VERSION 5.4 ;
NAMESCASESENSITIVE ON ;
BUSBITCHARS "[]" ;
DIVIDERCHAR "/" ;
UNITS
  DATABASE MICRONS 2000 ;
END UNITS
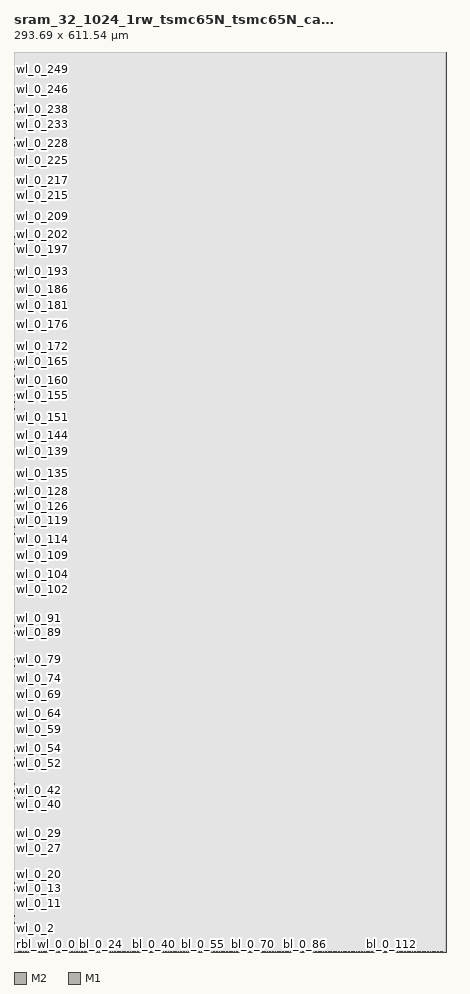
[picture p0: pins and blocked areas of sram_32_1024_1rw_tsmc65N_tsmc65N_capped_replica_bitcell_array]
MACRO sram_32_1024_1rw_tsmc65N_tsmc65N_capped_replica_bitcell_array
   CLASS BLOCK ;
   SIZE 293.69 BY 611.54 ;
   SYMMETRY X Y R90 ;
   PIN rbl_bl_0_0
      DIRECTION INOUT ;
      PORT
         LAYER M2 ;
         RECT  3.06 0.0 3.16 0.1 ;
      END
   END rbl_bl_0_0
   PIN rbl_br_0_0
      DIRECTION INOUT ;
      PORT
         LAYER M2 ;
         RECT  4.06 0.0 4.16 0.1 ;
      END
   END rbl_br_0_0
   PIN bl_0_0
      DIRECTION INOUT ;
      PORT
         LAYER M2 ;
         RECT  5.3 0.0 5.4 0.1 ;
      END
   END bl_0_0
   PIN br_0_0
      DIRECTION INOUT ;
      PORT
         LAYER M2 ;
         RECT  6.3 0.0 6.4 0.1 ;
      END
   END br_0_0
   PIN bl_0_1
      DIRECTION INOUT ;
      PORT
         LAYER M2 ;
         RECT  7.54 0.0 7.64 0.1 ;
      END
   END bl_0_1
   PIN br_0_1
      DIRECTION INOUT ;
      PORT
         LAYER M2 ;
         RECT  8.54 0.0 8.64 0.1 ;
      END
   END br_0_1
   PIN bl_0_2
      DIRECTION INOUT ;
      PORT
         LAYER M2 ;
         RECT  9.78 0.0 9.88 0.1 ;
      END
   END bl_0_2
   PIN br_0_2
      DIRECTION INOUT ;
      PORT
         LAYER M2 ;
         RECT  10.78 0.0 10.88 0.1 ;
      END
   END br_0_2
   PIN bl_0_3
      DIRECTION INOUT ;
      PORT
         LAYER M2 ;
         RECT  12.02 0.0 12.12 0.1 ;
      END
   END bl_0_3
   PIN br_0_3
      DIRECTION INOUT ;
      PORT
         LAYER M2 ;
         RECT  13.02 0.0 13.12 0.1 ;
      END
   END br_0_3
   PIN bl_0_4
      DIRECTION INOUT ;
      PORT
         LAYER M2 ;
         RECT  14.26 0.0 14.36 0.1 ;
      END
   END bl_0_4
   PIN br_0_4
      DIRECTION INOUT ;
      PORT
         LAYER M2 ;
         RECT  15.26 0.0 15.36 0.1 ;
      END
   END br_0_4
   PIN bl_0_5
      DIRECTION INOUT ;
      PORT
         LAYER M2 ;
         RECT  16.5 0.0 16.6 0.1 ;
      END
   END bl_0_5
   PIN br_0_5
      DIRECTION INOUT ;
      PORT
         LAYER M2 ;
         RECT  17.5 0.0 17.6 0.1 ;
      END
   END br_0_5
   PIN bl_0_6
      DIRECTION INOUT ;
      PORT
         LAYER M2 ;
         RECT  18.74 0.0 18.84 0.1 ;
      END
   END bl_0_6
   PIN br_0_6
      DIRECTION INOUT ;
      PORT
         LAYER M2 ;
         RECT  19.74 0.0 19.84 0.1 ;
      END
   END br_0_6
   PIN bl_0_7
      DIRECTION INOUT ;
      PORT
         LAYER M2 ;
         RECT  20.98 0.0 21.08 0.1 ;
      END
   END bl_0_7
   PIN br_0_7
      DIRECTION INOUT ;
      PORT
         LAYER M2 ;
         RECT  21.98 0.0 22.08 0.1 ;
      END
   END br_0_7
   PIN bl_0_8
      DIRECTION INOUT ;
      PORT
         LAYER M2 ;
         RECT  23.22 0.0 23.32 0.1 ;
      END
   END bl_0_8
   PIN br_0_8
      DIRECTION INOUT ;
      PORT
         LAYER M2 ;
         RECT  24.22 0.0 24.32 0.1 ;
      END
   END br_0_8
   PIN bl_0_9
      DIRECTION INOUT ;
      PORT
         LAYER M2 ;
         RECT  25.46 0.0 25.56 0.1 ;
      END
   END bl_0_9
   PIN br_0_9
      DIRECTION INOUT ;
      PORT
         LAYER M2 ;
         RECT  26.46 0.0 26.56 0.1 ;
      END
   END br_0_9
   PIN bl_0_10
      DIRECTION INOUT ;
      PORT
         LAYER M2 ;
         RECT  27.7 0.0 27.8 0.1 ;
      END
   END bl_0_10
   PIN br_0_10
      DIRECTION INOUT ;
      PORT
         LAYER M2 ;
         RECT  28.7 0.0 28.8 0.1 ;
      END
   END br_0_10
   PIN bl_0_11
      DIRECTION INOUT ;
      PORT
         LAYER M2 ;
         RECT  29.94 0.0 30.04 0.1 ;
      END
   END bl_0_11
   PIN br_0_11
      DIRECTION INOUT ;
      PORT
         LAYER M2 ;
         RECT  30.94 0.0 31.04 0.1 ;
      END
   END br_0_11
   PIN bl_0_12
      DIRECTION INOUT ;
      PORT
         LAYER M2 ;
         RECT  32.18 0.0 32.28 0.1 ;
      END
   END bl_0_12
   PIN br_0_12
      DIRECTION INOUT ;
      PORT
         LAYER M2 ;
         RECT  33.18 0.0 33.28 0.1 ;
      END
   END br_0_12
   PIN bl_0_13
      DIRECTION INOUT ;
      PORT
         LAYER M2 ;
         RECT  34.42 0.0 34.52 0.1 ;
      END
   END bl_0_13
   PIN br_0_13
      DIRECTION INOUT ;
      PORT
         LAYER M2 ;
         RECT  35.42 0.0 35.52 0.1 ;
      END
   END br_0_13
   PIN bl_0_14
      DIRECTION INOUT ;
      PORT
         LAYER M2 ;
         RECT  36.66 0.0 36.76 0.1 ;
      END
   END bl_0_14
   PIN br_0_14
      DIRECTION INOUT ;
      PORT
         LAYER M2 ;
         RECT  37.66 0.0 37.76 0.1 ;
      END
   END br_0_14
   PIN bl_0_15
      DIRECTION INOUT ;
      PORT
         LAYER M2 ;
         RECT  38.9 0.0 39.0 0.1 ;
      END
   END bl_0_15
   PIN br_0_15
      DIRECTION INOUT ;
      PORT
         LAYER M2 ;
         RECT  39.9 0.0 40.0 0.1 ;
      END
   END br_0_15
   PIN bl_0_16
      DIRECTION INOUT ;
      PORT
         LAYER M2 ;
         RECT  41.14 0.0 41.24 0.1 ;
      END
   END bl_0_16
   PIN br_0_16
      DIRECTION INOUT ;
      PORT
         LAYER M2 ;
         RECT  42.14 0.0 42.24 0.1 ;
      END
   END br_0_16
   PIN bl_0_17
      DIRECTION INOUT ;
      PORT
         LAYER M2 ;
         RECT  43.38 0.0 43.48 0.1 ;
      END
   END bl_0_17
   PIN br_0_17
      DIRECTION INOUT ;
      PORT
         LAYER M2 ;
         RECT  44.38 0.0 44.48 0.1 ;
      END
   END br_0_17
   PIN bl_0_18
      DIRECTION INOUT ;
      PORT
         LAYER M2 ;
         RECT  45.62 0.0 45.72 0.1 ;
      END
   END bl_0_18
   PIN br_0_18
      DIRECTION INOUT ;
      PORT
         LAYER M2 ;
         RECT  46.62 0.0 46.72 0.1 ;
      END
   END br_0_18
   PIN bl_0_19
      DIRECTION INOUT ;
      PORT
         LAYER M2 ;
         RECT  47.86 0.0 47.96 0.1 ;
      END
   END bl_0_19
   PIN br_0_19
      DIRECTION INOUT ;
      PORT
         LAYER M2 ;
         RECT  48.86 0.0 48.96 0.1 ;
      END
   END br_0_19
   PIN bl_0_20
      DIRECTION INOUT ;
      PORT
         LAYER M2 ;
         RECT  50.1 0.0 50.2 0.1 ;
      END
   END bl_0_20
   PIN br_0_20
      DIRECTION INOUT ;
      PORT
         LAYER M2 ;
         RECT  51.1 0.0 51.2 0.1 ;
      END
   END br_0_20
   PIN bl_0_21
      DIRECTION INOUT ;
      PORT
         LAYER M2 ;
         RECT  52.34 0.0 52.44 0.1 ;
      END
   END bl_0_21
   PIN br_0_21
      DIRECTION INOUT ;
      PORT
         LAYER M2 ;
         RECT  53.34 0.0 53.44 0.1 ;
      END
   END br_0_21
   PIN bl_0_22
      DIRECTION INOUT ;
      PORT
         LAYER M2 ;
         RECT  54.58 0.0 54.68 0.1 ;
      END
   END bl_0_22
   PIN br_0_22
      DIRECTION INOUT ;
      PORT
         LAYER M2 ;
         RECT  55.58 0.0 55.68 0.1 ;
      END
   END br_0_22
   PIN bl_0_23
      DIRECTION INOUT ;
      PORT
         LAYER M2 ;
         RECT  56.82 0.0 56.92 0.1 ;
      END
   END bl_0_23
   PIN br_0_23
      DIRECTION INOUT ;
      PORT
         LAYER M2 ;
         RECT  57.82 0.0 57.92 0.1 ;
      END
   END br_0_23
   PIN bl_0_24
      DIRECTION INOUT ;
      PORT
         LAYER M2 ;
         RECT  59.06 0.0 59.16 0.1 ;
      END
   END bl_0_24
   PIN br_0_24
      DIRECTION INOUT ;
      PORT
         LAYER M2 ;
         RECT  60.06 0.0 60.16 0.1 ;
      END
   END br_0_24
   PIN bl_0_25
      DIRECTION INOUT ;
      PORT
         LAYER M2 ;
         RECT  61.3 0.0 61.4 0.1 ;
      END
   END bl_0_25
   PIN br_0_25
      DIRECTION INOUT ;
      PORT
         LAYER M2 ;
         RECT  62.3 0.0 62.4 0.1 ;
      END
   END br_0_25
   PIN bl_0_26
      DIRECTION INOUT ;
      PORT
         LAYER M2 ;
         RECT  63.54 0.0 63.64 0.1 ;
      END
   END bl_0_26
   PIN br_0_26
      DIRECTION INOUT ;
      PORT
         LAYER M2 ;
         RECT  64.54 0.0 64.64 0.1 ;
      END
   END br_0_26
   PIN bl_0_27
      DIRECTION INOUT ;
      PORT
         LAYER M2 ;
         RECT  65.78 0.0 65.88 0.1 ;
      END
   END bl_0_27
   PIN br_0_27
      DIRECTION INOUT ;
      PORT
         LAYER M2 ;
         RECT  66.78 0.0 66.88 0.1 ;
      END
   END br_0_27
   PIN bl_0_28
      DIRECTION INOUT ;
      PORT
         LAYER M2 ;
         RECT  68.02 0.0 68.12 0.1 ;
      END
   END bl_0_28
   PIN br_0_28
      DIRECTION INOUT ;
      PORT
         LAYER M2 ;
         RECT  69.02 0.0 69.12 0.1 ;
      END
   END br_0_28
   PIN bl_0_29
      DIRECTION INOUT ;
      PORT
         LAYER M2 ;
         RECT  70.26 0.0 70.36 0.1 ;
      END
   END bl_0_29
   PIN br_0_29
      DIRECTION INOUT ;
      PORT
         LAYER M2 ;
         RECT  71.26 0.0 71.36 0.1 ;
      END
   END br_0_29
   PIN bl_0_30
      DIRECTION INOUT ;
      PORT
         LAYER M2 ;
         RECT  72.5 0.0 72.6 0.1 ;
      END
   END bl_0_30
   PIN br_0_30
      DIRECTION INOUT ;
      PORT
         LAYER M2 ;
         RECT  73.5 0.0 73.6 0.1 ;
      END
   END br_0_30
   PIN bl_0_31
      DIRECTION INOUT ;
      PORT
         LAYER M2 ;
         RECT  74.74 0.0 74.84 0.1 ;
      END
   END bl_0_31
   PIN br_0_31
      DIRECTION INOUT ;
      PORT
         LAYER M2 ;
         RECT  75.74 0.0 75.84 0.1 ;
      END
   END br_0_31
   PIN bl_0_32
      DIRECTION INOUT ;
      PORT
         LAYER M2 ;
         RECT  76.98 0.0 77.08 0.1 ;
      END
   END bl_0_32
   PIN br_0_32
      DIRECTION INOUT ;
      PORT
         LAYER M2 ;
         RECT  77.98 0.0 78.08 0.1 ;
      END
   END br_0_32
   PIN bl_0_33
      DIRECTION INOUT ;
      PORT
         LAYER M2 ;
         RECT  79.22 0.0 79.32 0.1 ;
      END
   END bl_0_33
   PIN br_0_33
      DIRECTION INOUT ;
      PORT
         LAYER M2 ;
         RECT  80.22 0.0 80.32 0.1 ;
      END
   END br_0_33
   PIN bl_0_34
      DIRECTION INOUT ;
      PORT
         LAYER M2 ;
         RECT  81.46 0.0 81.56 0.1 ;
      END
   END bl_0_34
   PIN br_0_34
      DIRECTION INOUT ;
      PORT
         LAYER M2 ;
         RECT  82.46 0.0 82.56 0.1 ;
      END
   END br_0_34
   PIN bl_0_35
      DIRECTION INOUT ;
      PORT
         LAYER M2 ;
         RECT  83.7 0.0 83.8 0.1 ;
      END
   END bl_0_35
   PIN br_0_35
      DIRECTION INOUT ;
      PORT
         LAYER M2 ;
         RECT  84.7 0.0 84.8 0.1 ;
      END
   END br_0_35
   PIN bl_0_36
      DIRECTION INOUT ;
      PORT
         LAYER M2 ;
         RECT  85.94 0.0 86.04 0.1 ;
      END
   END bl_0_36
   PIN br_0_36
      DIRECTION INOUT ;
      PORT
         LAYER M2 ;
         RECT  86.94 0.0 87.04 0.1 ;
      END
   END br_0_36
   PIN bl_0_37
      DIRECTION INOUT ;
      PORT
         LAYER M2 ;
         RECT  88.18 0.0 88.28 0.1 ;
      END
   END bl_0_37
   PIN br_0_37
      DIRECTION INOUT ;
      PORT
         LAYER M2 ;
         RECT  89.18 0.0 89.28 0.1 ;
      END
   END br_0_37
   PIN bl_0_38
      DIRECTION INOUT ;
      PORT
         LAYER M2 ;
         RECT  90.42 0.0 90.52 0.1 ;
      END
   END bl_0_38
   PIN br_0_38
      DIRECTION INOUT ;
      PORT
         LAYER M2 ;
         RECT  91.42 0.0 91.52 0.1 ;
      END
   END br_0_38
   PIN bl_0_39
      DIRECTION INOUT ;
      PORT
         LAYER M2 ;
         RECT  92.66 0.0 92.76 0.1 ;
      END
   END bl_0_39
   PIN br_0_39
      DIRECTION INOUT ;
      PORT
         LAYER M2 ;
         RECT  93.66 0.0 93.76 0.1 ;
      END
   END br_0_39
   PIN bl_0_40
      DIRECTION INOUT ;
      PORT
         LAYER M2 ;
         RECT  94.9 0.0 95.0 0.1 ;
      END
   END bl_0_40
   PIN br_0_40
      DIRECTION INOUT ;
      PORT
         LAYER M2 ;
         RECT  95.9 0.0 96.0 0.1 ;
      END
   END br_0_40
   PIN bl_0_41
      DIRECTION INOUT ;
      PORT
         LAYER M2 ;
         RECT  97.14 0.0 97.24 0.1 ;
      END
   END bl_0_41
   PIN br_0_41
      DIRECTION INOUT ;
      PORT
         LAYER M2 ;
         RECT  98.14 0.0 98.24 0.1 ;
      END
   END br_0_41
   PIN bl_0_42
      DIRECTION INOUT ;
      PORT
         LAYER M2 ;
         RECT  99.38 0.0 99.48 0.1 ;
      END
   END bl_0_42
   PIN br_0_42
      DIRECTION INOUT ;
      PORT
         LAYER M2 ;
         RECT  100.38 0.0 100.48 0.1 ;
      END
   END br_0_42
   PIN bl_0_43
      DIRECTION INOUT ;
      PORT
         LAYER M2 ;
         RECT  101.62 0.0 101.72 0.1 ;
      END
   END bl_0_43
   PIN br_0_43
      DIRECTION INOUT ;
      PORT
         LAYER M2 ;
         RECT  102.62 0.0 102.72 0.1 ;
      END
   END br_0_43
   PIN bl_0_44
      DIRECTION INOUT ;
      PORT
         LAYER M2 ;
         RECT  103.86 0.0 103.96 0.1 ;
      END
   END bl_0_44
   PIN br_0_44
      DIRECTION INOUT ;
      PORT
         LAYER M2 ;
         RECT  104.86 0.0 104.96 0.1 ;
      END
   END br_0_44
   PIN bl_0_45
      DIRECTION INOUT ;
      PORT
         LAYER M2 ;
         RECT  106.1 0.0 106.2 0.1 ;
      END
   END bl_0_45
   PIN br_0_45
      DIRECTION INOUT ;
      PORT
         LAYER M2 ;
         RECT  107.1 0.0 107.2 0.1 ;
      END
   END br_0_45
   PIN bl_0_46
      DIRECTION INOUT ;
      PORT
         LAYER M2 ;
         RECT  108.34 0.0 108.44 0.1 ;
      END
   END bl_0_46
   PIN br_0_46
      DIRECTION INOUT ;
      PORT
         LAYER M2 ;
         RECT  109.34 0.0 109.44 0.1 ;
      END
   END br_0_46
   PIN bl_0_47
      DIRECTION INOUT ;
      PORT
         LAYER M2 ;
         RECT  110.58 0.0 110.68 0.1 ;
      END
   END bl_0_47
   PIN br_0_47
      DIRECTION INOUT ;
      PORT
         LAYER M2 ;
         RECT  111.58 0.0 111.68 0.1 ;
      END
   END br_0_47
   PIN bl_0_48
      DIRECTION INOUT ;
      PORT
         LAYER M2 ;
         RECT  112.82 0.0 112.92 0.1 ;
      END
   END bl_0_48
   PIN br_0_48
      DIRECTION INOUT ;
      PORT
         LAYER M2 ;
         RECT  113.82 0.0 113.92 0.1 ;
      END
   END br_0_48
   PIN bl_0_49
      DIRECTION INOUT ;
      PORT
         LAYER M2 ;
         RECT  115.06 0.0 115.16 0.1 ;
      END
   END bl_0_49
   PIN br_0_49
      DIRECTION INOUT ;
      PORT
         LAYER M2 ;
         RECT  116.06 0.0 116.16 0.1 ;
      END
   END br_0_49
   PIN bl_0_50
      DIRECTION INOUT ;
      PORT
         LAYER M2 ;
         RECT  117.3 0.0 117.4 0.1 ;
      END
   END bl_0_50
   PIN br_0_50
      DIRECTION INOUT ;
      PORT
         LAYER M2 ;
         RECT  118.3 0.0 118.4 0.1 ;
      END
   END br_0_50
   PIN bl_0_51
      DIRECTION INOUT ;
      PORT
         LAYER M2 ;
         RECT  119.54 0.0 119.64 0.1 ;
      END
   END bl_0_51
   PIN br_0_51
      DIRECTION INOUT ;
      PORT
         LAYER M2 ;
         RECT  120.54 0.0 120.64 0.1 ;
      END
   END br_0_51
   PIN bl_0_52
      DIRECTION INOUT ;
      PORT
         LAYER M2 ;
         RECT  121.78 0.0 121.88 0.1 ;
      END
   END bl_0_52
   PIN br_0_52
      DIRECTION INOUT ;
      PORT
         LAYER M2 ;
         RECT  122.78 0.0 122.88 0.1 ;
      END
   END br_0_52
   PIN bl_0_53
      DIRECTION INOUT ;
      PORT
         LAYER M2 ;
         RECT  124.02 0.0 124.12 0.1 ;
      END
   END bl_0_53
   PIN br_0_53
      DIRECTION INOUT ;
      PORT
         LAYER M2 ;
         RECT  125.02 0.0 125.12 0.1 ;
      END
   END br_0_53
   PIN bl_0_54
      DIRECTION INOUT ;
      PORT
         LAYER M2 ;
         RECT  126.26 0.0 126.36 0.1 ;
      END
   END bl_0_54
   PIN br_0_54
      DIRECTION INOUT ;
      PORT
         LAYER M2 ;
         RECT  127.26 0.0 127.36 0.1 ;
      END
   END br_0_54
   PIN bl_0_55
      DIRECTION INOUT ;
      PORT
         LAYER M2 ;
         RECT  128.5 0.0 128.6 0.1 ;
      END
   END bl_0_55
   PIN br_0_55
      DIRECTION INOUT ;
      PORT
         LAYER M2 ;
         RECT  129.5 0.0 129.6 0.1 ;
      END
   END br_0_55
   PIN bl_0_56
      DIRECTION INOUT ;
      PORT
         LAYER M2 ;
         RECT  130.74 0.0 130.84 0.1 ;
      END
   END bl_0_56
   PIN br_0_56
      DIRECTION INOUT ;
      PORT
         LAYER M2 ;
         RECT  131.74 0.0 131.84 0.1 ;
      END
   END br_0_56
   PIN bl_0_57
      DIRECTION INOUT ;
      PORT
         LAYER M2 ;
         RECT  132.98 0.0 133.08 0.1 ;
      END
   END bl_0_57
   PIN br_0_57
      DIRECTION INOUT ;
      PORT
         LAYER M2 ;
         RECT  133.98 0.0 134.08 0.1 ;
      END
   END br_0_57
   PIN bl_0_58
      DIRECTION INOUT ;
      PORT
         LAYER M2 ;
         RECT  135.22 0.0 135.32 0.1 ;
      END
   END bl_0_58
   PIN br_0_58
      DIRECTION INOUT ;
      PORT
         LAYER M2 ;
         RECT  136.22 0.0 136.32 0.1 ;
      END
   END br_0_58
   PIN bl_0_59
      DIRECTION INOUT ;
      PORT
         LAYER M2 ;
         RECT  137.46 0.0 137.56 0.1 ;
      END
   END bl_0_59
   PIN br_0_59
      DIRECTION INOUT ;
      PORT
         LAYER M2 ;
         RECT  138.46 0.0 138.56 0.1 ;
      END
   END br_0_59
   PIN bl_0_60
      DIRECTION INOUT ;
      PORT
         LAYER M2 ;
         RECT  139.7 0.0 139.8 0.1 ;
      END
   END bl_0_60
   PIN br_0_60
      DIRECTION INOUT ;
      PORT
         LAYER M2 ;
         RECT  140.7 0.0 140.8 0.1 ;
      END
   END br_0_60
   PIN bl_0_61
      DIRECTION INOUT ;
      PORT
         LAYER M2 ;
         RECT  141.94 0.0 142.04 0.1 ;
      END
   END bl_0_61
   PIN br_0_61
      DIRECTION INOUT ;
      PORT
         LAYER M2 ;
         RECT  142.94 0.0 143.04 0.1 ;
      END
   END br_0_61
   PIN bl_0_62
      DIRECTION INOUT ;
      PORT
         LAYER M2 ;
         RECT  144.18 0.0 144.28 0.1 ;
      END
   END bl_0_62
   PIN br_0_62
      DIRECTION INOUT ;
      PORT
         LAYER M2 ;
         RECT  145.18 0.0 145.28 0.1 ;
      END
   END br_0_62
   PIN bl_0_63
      DIRECTION INOUT ;
      PORT
         LAYER M2 ;
         RECT  146.42 0.0 146.52 0.1 ;
      END
   END bl_0_63
   PIN br_0_63
      DIRECTION INOUT ;
      PORT
         LAYER M2 ;
         RECT  147.42 0.0 147.52 0.1 ;
      END
   END br_0_63
   PIN bl_0_64
      DIRECTION INOUT ;
      PORT
         LAYER M2 ;
         RECT  148.66 0.0 148.76 0.1 ;
      END
   END bl_0_64
   PIN br_0_64
      DIRECTION INOUT ;
      PORT
         LAYER M2 ;
         RECT  149.66 0.0 149.76 0.1 ;
      END
   END br_0_64
   PIN bl_0_65
      DIRECTION INOUT ;
      PORT
         LAYER M2 ;
         RECT  150.9 0.0 151.0 0.1 ;
      END
   END bl_0_65
   PIN br_0_65
      DIRECTION INOUT ;
      PORT
         LAYER M2 ;
         RECT  151.9 0.0 152.0 0.1 ;
      END
   END br_0_65
   PIN bl_0_66
      DIRECTION INOUT ;
      PORT
         LAYER M2 ;
         RECT  153.14 0.0 153.24 0.1 ;
      END
   END bl_0_66
   PIN br_0_66
      DIRECTION INOUT ;
      PORT
         LAYER M2 ;
         RECT  154.14 0.0 154.24 0.1 ;
      END
   END br_0_66
   PIN bl_0_67
      DIRECTION INOUT ;
      PORT
         LAYER M2 ;
         RECT  155.38 0.0 155.48 0.1 ;
      END
   END bl_0_67
   PIN br_0_67
      DIRECTION INOUT ;
      PORT
         LAYER M2 ;
         RECT  156.38 0.0 156.48 0.1 ;
      END
   END br_0_67
   PIN bl_0_68
      DIRECTION INOUT ;
      PORT
         LAYER M2 ;
         RECT  157.62 0.0 157.72 0.1 ;
      END
   END bl_0_68
   PIN br_0_68
      DIRECTION INOUT ;
      PORT
         LAYER M2 ;
         RECT  158.62 0.0 158.72 0.1 ;
      END
   END br_0_68
   PIN bl_0_69
      DIRECTION INOUT ;
      PORT
         LAYER M2 ;
         RECT  159.86 0.0 159.96 0.1 ;
      END
   END bl_0_69
   PIN br_0_69
      DIRECTION INOUT ;
      PORT
         LAYER M2 ;
         RECT  160.86 0.0 160.96 0.1 ;
      END
   END br_0_69
   PIN bl_0_70
      DIRECTION INOUT ;
      PORT
         LAYER M2 ;
         RECT  162.1 0.0 162.2 0.1 ;
      END
   END bl_0_70
   PIN br_0_70
      DIRECTION INOUT ;
      PORT
         LAYER M2 ;
         RECT  163.1 0.0 163.2 0.1 ;
      END
   END br_0_70
   PIN bl_0_71
      DIRECTION INOUT ;
      PORT
         LAYER M2 ;
         RECT  164.34 0.0 164.44 0.1 ;
      END
   END bl_0_71
   PIN br_0_71
      DIRECTION INOUT ;
      PORT
         LAYER M2 ;
         RECT  165.34 0.0 165.44 0.1 ;
      END
   END br_0_71
   PIN bl_0_72
      DIRECTION INOUT ;
      PORT
         LAYER M2 ;
         RECT  166.58 0.0 166.68 0.1 ;
      END
   END bl_0_72
   PIN br_0_72
      DIRECTION INOUT ;
      PORT
         LAYER M2 ;
         RECT  167.58 0.0 167.68 0.1 ;
      END
   END br_0_72
   PIN bl_0_73
      DIRECTION INOUT ;
      PORT
         LAYER M2 ;
         RECT  168.82 0.0 168.92 0.1 ;
      END
   END bl_0_73
   PIN br_0_73
      DIRECTION INOUT ;
      PORT
         LAYER M2 ;
         RECT  169.82 0.0 169.92 0.1 ;
      END
   END br_0_73
   PIN bl_0_74
      DIRECTION INOUT ;
      PORT
         LAYER M2 ;
         RECT  171.06 0.0 171.16 0.1 ;
      END
   END bl_0_74
   PIN br_0_74
      DIRECTION INOUT ;
      PORT
         LAYER M2 ;
         RECT  172.06 0.0 172.16 0.1 ;
      END
   END br_0_74
   PIN bl_0_75
      DIRECTION INOUT ;
      PORT
         LAYER M2 ;
         RECT  173.3 0.0 173.4 0.1 ;
      END
   END bl_0_75
   PIN br_0_75
      DIRECTION INOUT ;
      PORT
         LAYER M2 ;
         RECT  174.3 0.0 174.4 0.1 ;
      END
   END br_0_75
   PIN bl_0_76
      DIRECTION INOUT ;
      PORT
         LAYER M2 ;
         RECT  175.54 0.0 175.64 0.1 ;
      END
   END bl_0_76
   PIN br_0_76
      DIRECTION INOUT ;
      PORT
         LAYER M2 ;
         RECT  176.54 0.0 176.64 0.1 ;
      END
   END br_0_76
   PIN bl_0_77
      DIRECTION INOUT ;
      PORT
         LAYER M2 ;
         RECT  177.78 0.0 177.88 0.1 ;
      END
   END bl_0_77
   PIN br_0_77
      DIRECTION INOUT ;
      PORT
         LAYER M2 ;
         RECT  178.78 0.0 178.88 0.1 ;
      END
   END br_0_77
   PIN bl_0_78
      DIRECTION INOUT ;
      PORT
         LAYER M2 ;
         RECT  180.02 0.0 180.12 0.1 ;
      END
   END bl_0_78
   PIN br_0_78
      DIRECTION INOUT ;
      PORT
         LAYER M2 ;
         RECT  181.02 0.0 181.12 0.1 ;
      END
   END br_0_78
   PIN bl_0_79
      DIRECTION INOUT ;
      PORT
         LAYER M2 ;
         RECT  182.26 0.0 182.36 0.1 ;
      END
   END bl_0_79
   PIN br_0_79
      DIRECTION INOUT ;
      PORT
         LAYER M2 ;
         RECT  183.26 0.0 183.36 0.1 ;
      END
   END br_0_79
   PIN bl_0_80
      DIRECTION INOUT ;
      PORT
         LAYER M2 ;
         RECT  184.5 0.0 184.6 0.1 ;
      END
   END bl_0_80
   PIN br_0_80
      DIRECTION INOUT ;
      PORT
         LAYER M2 ;
         RECT  185.5 0.0 185.6 0.1 ;
      END
   END br_0_80
   PIN bl_0_81
      DIRECTION INOUT ;
      PORT
         LAYER M2 ;
         RECT  186.74 0.0 186.84 0.1 ;
      END
   END bl_0_81
   PIN br_0_81
      DIRECTION INOUT ;
      PORT
         LAYER M2 ;
         RECT  187.74 0.0 187.84 0.1 ;
      END
   END br_0_81
   PIN bl_0_82
      DIRECTION INOUT ;
      PORT
         LAYER M2 ;
         RECT  188.98 0.0 189.08 0.1 ;
      END
   END bl_0_82
   PIN br_0_82
      DIRECTION INOUT ;
      PORT
         LAYER M2 ;
         RECT  189.98 0.0 190.08 0.1 ;
      END
   END br_0_82
   PIN bl_0_83
      DIRECTION INOUT ;
      PORT
         LAYER M2 ;
         RECT  191.22 0.0 191.32 0.1 ;
      END
   END bl_0_83
   PIN br_0_83
      DIRECTION INOUT ;
      PORT
         LAYER M2 ;
         RECT  192.22 0.0 192.32 0.1 ;
      END
   END br_0_83
   PIN bl_0_84
      DIRECTION INOUT ;
      PORT
         LAYER M2 ;
         RECT  193.46 0.0 193.56 0.1 ;
      END
   END bl_0_84
   PIN br_0_84
      DIRECTION INOUT ;
      PORT
         LAYER M2 ;
         RECT  194.46 0.0 194.56 0.1 ;
      END
   END br_0_84
   PIN bl_0_85
      DIRECTION INOUT ;
      PORT
         LAYER M2 ;
         RECT  195.7 0.0 195.8 0.1 ;
      END
   END bl_0_85
   PIN br_0_85
      DIRECTION INOUT ;
      PORT
         LAYER M2 ;
         RECT  196.7 0.0 196.8 0.1 ;
      END
   END br_0_85
   PIN bl_0_86
      DIRECTION INOUT ;
      PORT
         LAYER M2 ;
         RECT  197.94 0.0 198.04 0.1 ;
      END
   END bl_0_86
   PIN br_0_86
      DIRECTION INOUT ;
      PORT
         LAYER M2 ;
         RECT  198.94 0.0 199.04 0.1 ;
      END
   END br_0_86
   PIN bl_0_87
      DIRECTION INOUT ;
      PORT
         LAYER M2 ;
         RECT  200.18 0.0 200.28 0.1 ;
      END
   END bl_0_87
   PIN br_0_87
      DIRECTION INOUT ;
      PORT
         LAYER M2 ;
         RECT  201.18 0.0 201.28 0.1 ;
      END
   END br_0_87
   PIN bl_0_88
      DIRECTION INOUT ;
      PORT
         LAYER M2 ;
         RECT  202.42 0.0 202.52 0.1 ;
      END
   END bl_0_88
   PIN br_0_88
      DIRECTION INOUT ;
      PORT
         LAYER M2 ;
         RECT  203.42 0.0 203.52 0.1 ;
      END
   END br_0_88
   PIN bl_0_89
      DIRECTION INOUT ;
      PORT
         LAYER M2 ;
         RECT  204.66 0.0 204.76 0.1 ;
      END
   END bl_0_89
   PIN br_0_89
      DIRECTION INOUT ;
      PORT
         LAYER M2 ;
         RECT  205.66 0.0 205.76 0.1 ;
      END
   END br_0_89
   PIN bl_0_90
      DIRECTION INOUT ;
      PORT
         LAYER M2 ;
         RECT  206.9 0.0 207.0 0.1 ;
      END
   END bl_0_90
   PIN br_0_90
      DIRECTION INOUT ;
      PORT
         LAYER M2 ;
         RECT  207.9 0.0 208.0 0.1 ;
      END
   END br_0_90
   PIN bl_0_91
      DIRECTION INOUT ;
      PORT
         LAYER M2 ;
         RECT  209.14 0.0 209.24 0.1 ;
      END
   END bl_0_91
   PIN br_0_91
      DIRECTION INOUT ;
      PORT
         LAYER M2 ;
         RECT  210.14 0.0 210.24 0.1 ;
      END
   END br_0_91
   PIN bl_0_92
      DIRECTION INOUT ;
      PORT
         LAYER M2 ;
         RECT  211.38 0.0 211.48 0.1 ;
      END
   END bl_0_92
   PIN br_0_92
      DIRECTION INOUT ;
      PORT
         LAYER M2 ;
         RECT  212.38 0.0 212.48 0.1 ;
      END
   END br_0_92
   PIN bl_0_93
      DIRECTION INOUT ;
      PORT
         LAYER M2 ;
         RECT  213.62 0.0 213.72 0.1 ;
      END
   END bl_0_93
   PIN br_0_93
      DIRECTION INOUT ;
      PORT
         LAYER M2 ;
         RECT  214.62 0.0 214.72 0.1 ;
      END
   END br_0_93
   PIN bl_0_94
      DIRECTION INOUT ;
      PORT
         LAYER M2 ;
         RECT  215.86 0.0 215.96 0.1 ;
      END
   END bl_0_94
   PIN br_0_94
      DIRECTION INOUT ;
      PORT
         LAYER M2 ;
         RECT  216.86 0.0 216.96 0.1 ;
      END
   END br_0_94
   PIN bl_0_95
      DIRECTION INOUT ;
      PORT
         LAYER M2 ;
         RECT  218.1 0.0 218.2 0.1 ;
      END
   END bl_0_95
   PIN br_0_95
      DIRECTION INOUT ;
      PORT
         LAYER M2 ;
         RECT  219.1 0.0 219.2 0.1 ;
      END
   END br_0_95
   PIN bl_0_96
      DIRECTION INOUT ;
      PORT
         LAYER M2 ;
         RECT  220.34 0.0 220.44 0.1 ;
      END
   END bl_0_96
   PIN br_0_96
      DIRECTION INOUT ;
      PORT
         LAYER M2 ;
         RECT  221.34 0.0 221.44 0.1 ;
      END
   END br_0_96
   PIN bl_0_97
      DIRECTION INOUT ;
      PORT
         LAYER M2 ;
         RECT  222.58 0.0 222.68 0.1 ;
      END
   END bl_0_97
   PIN br_0_97
      DIRECTION INOUT ;
      PORT
         LAYER M2 ;
         RECT  223.58 0.0 223.68 0.1 ;
      END
   END br_0_97
   PIN bl_0_98
      DIRECTION INOUT ;
      PORT
         LAYER M2 ;
         RECT  224.82 0.0 224.92 0.1 ;
      END
   END bl_0_98
   PIN br_0_98
      DIRECTION INOUT ;
      PORT
         LAYER M2 ;
         RECT  225.82 0.0 225.92 0.1 ;
      END
   END br_0_98
   PIN bl_0_99
      DIRECTION INOUT ;
      PORT
         LAYER M2 ;
         RECT  227.06 0.0 227.16 0.1 ;
      END
   END bl_0_99
   PIN br_0_99
      DIRECTION INOUT ;
      PORT
         LAYER M2 ;
         RECT  228.06 0.0 228.16 0.1 ;
      END
   END br_0_99
   PIN bl_0_100
      DIRECTION INOUT ;
      PORT
         LAYER M2 ;
         RECT  229.3 0.0 229.4 0.1 ;
      END
   END bl_0_100
   PIN br_0_100
      DIRECTION INOUT ;
      PORT
         LAYER M2 ;
         RECT  230.3 0.0 230.4 0.1 ;
      END
   END br_0_100
   PIN bl_0_101
      DIRECTION INOUT ;
      PORT
         LAYER M2 ;
         RECT  231.54 0.0 231.64 0.1 ;
      END
   END bl_0_101
   PIN br_0_101
      DIRECTION INOUT ;
      PORT
         LAYER M2 ;
         RECT  232.54 0.0 232.64 0.1 ;
      END
   END br_0_101
   PIN bl_0_102
      DIRECTION INOUT ;
      PORT
         LAYER M2 ;
         RECT  233.78 0.0 233.88 0.1 ;
      END
   END bl_0_102
   PIN br_0_102
      DIRECTION INOUT ;
      PORT
         LAYER M2 ;
         RECT  234.78 0.0 234.88 0.1 ;
      END
   END br_0_102
   PIN bl_0_103
      DIRECTION INOUT ;
      PORT
         LAYER M2 ;
         RECT  236.02 0.0 236.12 0.1 ;
      END
   END bl_0_103
   PIN br_0_103
      DIRECTION INOUT ;
      PORT
         LAYER M2 ;
         RECT  237.02 0.0 237.12 0.1 ;
      END
   END br_0_103
   PIN bl_0_104
      DIRECTION INOUT ;
      PORT
         LAYER M2 ;
         RECT  238.26 0.0 238.36 0.1 ;
      END
   END bl_0_104
   PIN br_0_104
      DIRECTION INOUT ;
      PORT
         LAYER M2 ;
         RECT  239.26 0.0 239.36 0.1 ;
      END
   END br_0_104
   PIN bl_0_105
      DIRECTION INOUT ;
      PORT
         LAYER M2 ;
         RECT  240.5 0.0 240.6 0.1 ;
      END
   END bl_0_105
   PIN br_0_105
      DIRECTION INOUT ;
      PORT
         LAYER M2 ;
         RECT  241.5 0.0 241.6 0.1 ;
      END
   END br_0_105
   PIN bl_0_106
      DIRECTION INOUT ;
      PORT
         LAYER M2 ;
         RECT  242.74 0.0 242.84 0.1 ;
      END
   END bl_0_106
   PIN br_0_106
      DIRECTION INOUT ;
      PORT
         LAYER M2 ;
         RECT  243.74 0.0 243.84 0.1 ;
      END
   END br_0_106
   PIN bl_0_107
      DIRECTION INOUT ;
      PORT
         LAYER M2 ;
         RECT  244.98 0.0 245.08 0.1 ;
      END
   END bl_0_107
   PIN br_0_107
      DIRECTION INOUT ;
      PORT
         LAYER M2 ;
         RECT  245.98 0.0 246.08 0.1 ;
      END
   END br_0_107
   PIN bl_0_108
      DIRECTION INOUT ;
      PORT
         LAYER M2 ;
         RECT  247.22 0.0 247.32 0.1 ;
      END
   END bl_0_108
   PIN br_0_108
      DIRECTION INOUT ;
      PORT
         LAYER M2 ;
         RECT  248.22 0.0 248.32 0.1 ;
      END
   END br_0_108
   PIN bl_0_109
      DIRECTION INOUT ;
      PORT
         LAYER M2 ;
         RECT  249.46 0.0 249.56 0.1 ;
      END
   END bl_0_109
   PIN br_0_109
      DIRECTION INOUT ;
      PORT
         LAYER M2 ;
         RECT  250.46 0.0 250.56 0.1 ;
      END
   END br_0_109
   PIN bl_0_110
      DIRECTION INOUT ;
      PORT
         LAYER M2 ;
         RECT  251.7 0.0 251.8 0.1 ;
      END
   END bl_0_110
   PIN br_0_110
      DIRECTION INOUT ;
      PORT
         LAYER M2 ;
         RECT  252.7 0.0 252.8 0.1 ;
      END
   END br_0_110
   PIN bl_0_111
      DIRECTION INOUT ;
      PORT
         LAYER M2 ;
         RECT  253.94 0.0 254.04 0.1 ;
      END
   END bl_0_111
   PIN br_0_111
      DIRECTION INOUT ;
      PORT
         LAYER M2 ;
         RECT  254.94 0.0 255.04 0.1 ;
      END
   END br_0_111
   PIN bl_0_112
      DIRECTION INOUT ;
      PORT
         LAYER M2 ;
         RECT  256.18 0.0 256.28 0.1 ;
      END
   END bl_0_112
   PIN br_0_112
      DIRECTION INOUT ;
      PORT
         LAYER M2 ;
         RECT  257.18 0.0 257.28 0.1 ;
      END
   END br_0_112
   PIN bl_0_113
      DIRECTION INOUT ;
      PORT
         LAYER M2 ;
         RECT  258.42 0.0 258.52 0.1 ;
      END
   END bl_0_113
   PIN br_0_113
      DIRECTION INOUT ;
      PORT
         LAYER M2 ;
         RECT  259.42 0.0 259.52 0.1 ;
      END
   END br_0_113
   PIN bl_0_114
      DIRECTION INOUT ;
      PORT
         LAYER M2 ;
         RECT  260.66 0.0 260.76 0.1 ;
      END
   END bl_0_114
   PIN br_0_114
      DIRECTION INOUT ;
      PORT
         LAYER M2 ;
         RECT  261.66 0.0 261.76 0.1 ;
      END
   END br_0_114
   PIN bl_0_115
      DIRECTION INOUT ;
      PORT
         LAYER M2 ;
         RECT  262.9 0.0 263.0 0.1 ;
      END
   END bl_0_115
   PIN br_0_115
      DIRECTION INOUT ;
      PORT
         LAYER M2 ;
         RECT  263.9 0.0 264.0 0.1 ;
      END
   END br_0_115
   PIN bl_0_116
      DIRECTION INOUT ;
      PORT
         LAYER M2 ;
         RECT  265.14 0.0 265.24 0.1 ;
      END
   END bl_0_116
   PIN br_0_116
      DIRECTION INOUT ;
      PORT
         LAYER M2 ;
         RECT  266.14 0.0 266.24 0.1 ;
      END
   END br_0_116
   PIN bl_0_117
      DIRECTION INOUT ;
      PORT
         LAYER M2 ;
         RECT  267.38 0.0 267.48 0.1 ;
      END
   END bl_0_117
   PIN br_0_117
      DIRECTION INOUT ;
      PORT
         LAYER M2 ;
         RECT  268.38 0.0 268.48 0.1 ;
      END
   END br_0_117
   PIN bl_0_118
      DIRECTION INOUT ;
      PORT
         LAYER M2 ;
         RECT  269.62 0.0 269.72 0.1 ;
      END
   END bl_0_118
   PIN br_0_118
      DIRECTION INOUT ;
      PORT
         LAYER M2 ;
         RECT  270.62 0.0 270.72 0.1 ;
      END
   END br_0_118
   PIN bl_0_119
      DIRECTION INOUT ;
      PORT
         LAYER M2 ;
         RECT  271.86 0.0 271.96 0.1 ;
      END
   END bl_0_119
   PIN br_0_119
      DIRECTION INOUT ;
      PORT
         LAYER M2 ;
         RECT  272.86 0.0 272.96 0.1 ;
      END
   END br_0_119
   PIN bl_0_120
      DIRECTION INOUT ;
      PORT
         LAYER M2 ;
         RECT  274.1 0.0 274.2 0.1 ;
      END
   END bl_0_120
   PIN br_0_120
      DIRECTION INOUT ;
      PORT
         LAYER M2 ;
         RECT  275.1 0.0 275.2 0.1 ;
      END
   END br_0_120
   PIN bl_0_121
      DIRECTION INOUT ;
      PORT
         LAYER M2 ;
         RECT  276.34 0.0 276.44 0.1 ;
      END
   END bl_0_121
   PIN br_0_121
      DIRECTION INOUT ;
      PORT
         LAYER M2 ;
         RECT  277.34 0.0 277.44 0.1 ;
      END
   END br_0_121
   PIN bl_0_122
      DIRECTION INOUT ;
      PORT
         LAYER M2 ;
         RECT  278.58 0.0 278.68 0.1 ;
      END
   END bl_0_122
   PIN br_0_122
      DIRECTION INOUT ;
      PORT
         LAYER M2 ;
         RECT  279.58 0.0 279.68 0.1 ;
      END
   END br_0_122
   PIN bl_0_123
      DIRECTION INOUT ;
      PORT
         LAYER M2 ;
         RECT  280.82 0.0 280.92 0.1 ;
      END
   END bl_0_123
   PIN br_0_123
      DIRECTION INOUT ;
      PORT
         LAYER M2 ;
         RECT  281.82 0.0 281.92 0.1 ;
      END
   END br_0_123
   PIN bl_0_124
      DIRECTION INOUT ;
      PORT
         LAYER M2 ;
         RECT  283.06 0.0 283.16 0.1 ;
      END
   END bl_0_124
   PIN br_0_124
      DIRECTION INOUT ;
      PORT
         LAYER M2 ;
         RECT  284.06 0.0 284.16 0.1 ;
      END
   END br_0_124
   PIN bl_0_125
      DIRECTION INOUT ;
      PORT
         LAYER M2 ;
         RECT  285.3 0.0 285.4 0.1 ;
      END
   END bl_0_125
   PIN br_0_125
      DIRECTION INOUT ;
      PORT
         LAYER M2 ;
         RECT  286.3 0.0 286.4 0.1 ;
      END
   END br_0_125
   PIN bl_0_126
      DIRECTION INOUT ;
      PORT
         LAYER M2 ;
         RECT  287.54 0.0 287.64 0.1 ;
      END
   END bl_0_126
   PIN br_0_126
      DIRECTION INOUT ;
      PORT
         LAYER M2 ;
         RECT  288.54 0.0 288.64 0.1 ;
      END
   END br_0_126
   PIN bl_0_127
      DIRECTION INOUT ;
      PORT
         LAYER M2 ;
         RECT  289.78 0.0 289.88 0.1 ;
      END
   END bl_0_127
   PIN br_0_127
      DIRECTION INOUT ;
      PORT
         LAYER M2 ;
         RECT  290.78 0.0 290.88 0.1 ;
      END
   END br_0_127
   PIN rbl_wl_0_0
      DIRECTION INPUT ;
      PORT
         LAYER M1 ;
         RECT  0.0 4.335 0.09 4.425 ;
      END
   END rbl_wl_0_0
   PIN wl_0_0
      DIRECTION INPUT ;
      PORT
         LAYER M1 ;
         RECT  0.0 5.515 0.09 5.605 ;
      END
   END wl_0_0
   PIN wl_0_1
      DIRECTION INPUT ;
      PORT
         LAYER M1 ;
         RECT  0.0 9.055 0.09 9.145 ;
      END
   END wl_0_1
   PIN wl_0_2
      DIRECTION INPUT ;
      PORT
         LAYER M1 ;
         RECT  0.0 10.235 0.09 10.325 ;
      END
   END wl_0_2
   PIN wl_0_3
      DIRECTION INPUT ;
      PORT
         LAYER M1 ;
         RECT  0.0 13.775 0.09 13.865 ;
      END
   END wl_0_3
   PIN wl_0_4
      DIRECTION INPUT ;
      PORT
         LAYER M1 ;
         RECT  0.0 14.955 0.09 15.045 ;
      END
   END wl_0_4
   PIN wl_0_5
      DIRECTION INPUT ;
      PORT
         LAYER M1 ;
         RECT  0.0 18.495 0.09 18.585 ;
      END
   END wl_0_5
   PIN wl_0_6
      DIRECTION INPUT ;
      PORT
         LAYER M1 ;
         RECT  0.0 19.675 0.09 19.765 ;
      END
   END wl_0_6
   PIN wl_0_7
      DIRECTION INPUT ;
      PORT
         LAYER M1 ;
         RECT  0.0 23.215 0.09 23.305 ;
      END
   END wl_0_7
   PIN wl_0_8
      DIRECTION INPUT ;
      PORT
         LAYER M1 ;
         RECT  0.0 24.395 0.09 24.485 ;
      END
   END wl_0_8
   PIN wl_0_9
      DIRECTION INPUT ;
      PORT
         LAYER M1 ;
         RECT  0.0 27.935 0.09 28.025 ;
      END
   END wl_0_9
   PIN wl_0_10
      DIRECTION INPUT ;
      PORT
         LAYER M1 ;
         RECT  0.0 29.115 0.09 29.205 ;
      END
   END wl_0_10
   PIN wl_0_11
      DIRECTION INPUT ;
      PORT
         LAYER M1 ;
         RECT  0.0 32.655 0.09 32.745 ;
      END
   END wl_0_11
   PIN wl_0_12
      DIRECTION INPUT ;
      PORT
         LAYER M1 ;
         RECT  0.0 33.835 0.09 33.925 ;
      END
   END wl_0_12
   PIN wl_0_13
      DIRECTION INPUT ;
      PORT
         LAYER M1 ;
         RECT  0.0 37.375 0.09 37.465 ;
      END
   END wl_0_13
   PIN wl_0_14
      DIRECTION INPUT ;
      PORT
         LAYER M1 ;
         RECT  0.0 38.555 0.09 38.645 ;
      END
   END wl_0_14
   PIN wl_0_15
      DIRECTION INPUT ;
      PORT
         LAYER M1 ;
         RECT  0.0 42.095 0.09 42.185 ;
      END
   END wl_0_15
   PIN wl_0_16
      DIRECTION INPUT ;
      PORT
         LAYER M1 ;
         RECT  0.0 43.275 0.09 43.365 ;
      END
   END wl_0_16
   PIN wl_0_17
      DIRECTION INPUT ;
      PORT
         LAYER M1 ;
         RECT  0.0 46.815 0.09 46.905 ;
      END
   END wl_0_17
   PIN wl_0_18
      DIRECTION INPUT ;
      PORT
         LAYER M1 ;
         RECT  0.0 47.995 0.09 48.085 ;
      END
   END wl_0_18
   PIN wl_0_19
      DIRECTION INPUT ;
      PORT
         LAYER M1 ;
         RECT  0.0 51.535 0.09 51.625 ;
      END
   END wl_0_19
   PIN wl_0_20
      DIRECTION INPUT ;
      PORT
         LAYER M1 ;
         RECT  0.0 52.715 0.09 52.805 ;
      END
   END wl_0_20
   PIN wl_0_21
      DIRECTION INPUT ;
      PORT
         LAYER M1 ;
         RECT  0.0 56.255 0.09 56.345 ;
      END
   END wl_0_21
   PIN wl_0_22
      DIRECTION INPUT ;
      PORT
         LAYER M1 ;
         RECT  0.0 57.435 0.09 57.525 ;
      END
   END wl_0_22
   PIN wl_0_23
      DIRECTION INPUT ;
      PORT
         LAYER M1 ;
         RECT  0.0 60.975 0.09 61.065 ;
      END
   END wl_0_23
   PIN wl_0_24
      DIRECTION INPUT ;
      PORT
         LAYER M1 ;
         RECT  0.0 62.155 0.09 62.245 ;
      END
   END wl_0_24
   PIN wl_0_25
      DIRECTION INPUT ;
      PORT
         LAYER M1 ;
         RECT  0.0 65.695 0.09 65.785 ;
      END
   END wl_0_25
   PIN wl_0_26
      DIRECTION INPUT ;
      PORT
         LAYER M1 ;
         RECT  0.0 66.875 0.09 66.965 ;
      END
   END wl_0_26
   PIN wl_0_27
      DIRECTION INPUT ;
      PORT
         LAYER M1 ;
         RECT  0.0 70.415 0.09 70.505 ;
      END
   END wl_0_27
   PIN wl_0_28
      DIRECTION INPUT ;
      PORT
         LAYER M1 ;
         RECT  0.0 71.595 0.09 71.685 ;
      END
   END wl_0_28
   PIN wl_0_29
      DIRECTION INPUT ;
      PORT
         LAYER M1 ;
         RECT  0.0 75.135 0.09 75.225 ;
      END
   END wl_0_29
   PIN wl_0_30
      DIRECTION INPUT ;
      PORT
         LAYER M1 ;
         RECT  0.0 76.315 0.09 76.405 ;
      END
   END wl_0_30
   PIN wl_0_31
      DIRECTION INPUT ;
      PORT
         LAYER M1 ;
         RECT  0.0 79.855 0.09 79.945 ;
      END
   END wl_0_31
   PIN wl_0_32
      DIRECTION INPUT ;
      PORT
         LAYER M1 ;
         RECT  0.0 81.035 0.09 81.125 ;
      END
   END wl_0_32
   PIN wl_0_33
      DIRECTION INPUT ;
      PORT
         LAYER M1 ;
         RECT  0.0 84.575 0.09 84.665 ;
      END
   END wl_0_33
   PIN wl_0_34
      DIRECTION INPUT ;
      PORT
         LAYER M1 ;
         RECT  0.0 85.755 0.09 85.845 ;
      END
   END wl_0_34
   PIN wl_0_35
      DIRECTION INPUT ;
      PORT
         LAYER M1 ;
         RECT  0.0 89.295 0.09 89.385 ;
      END
   END wl_0_35
   PIN wl_0_36
      DIRECTION INPUT ;
      PORT
         LAYER M1 ;
         RECT  0.0 90.475 0.09 90.565 ;
      END
   END wl_0_36
   PIN wl_0_37
      DIRECTION INPUT ;
      PORT
         LAYER M1 ;
         RECT  0.0 94.015 0.09 94.105 ;
      END
   END wl_0_37
   PIN wl_0_38
      DIRECTION INPUT ;
      PORT
         LAYER M1 ;
         RECT  0.0 95.195 0.09 95.285 ;
      END
   END wl_0_38
   PIN wl_0_39
      DIRECTION INPUT ;
      PORT
         LAYER M1 ;
         RECT  0.0 98.735 0.09 98.825 ;
      END
   END wl_0_39
   PIN wl_0_40
      DIRECTION INPUT ;
      PORT
         LAYER M1 ;
         RECT  0.0 99.915 0.09 100.005 ;
      END
   END wl_0_40
   PIN wl_0_41
      DIRECTION INPUT ;
      PORT
         LAYER M1 ;
         RECT  0.0 103.455 0.09 103.545 ;
      END
   END wl_0_41
   PIN wl_0_42
      DIRECTION INPUT ;
      PORT
         LAYER M1 ;
         RECT  0.0 104.635 0.09 104.725 ;
      END
   END wl_0_42
   PIN wl_0_43
      DIRECTION INPUT ;
      PORT
         LAYER M1 ;
         RECT  0.0 108.175 0.09 108.265 ;
      END
   END wl_0_43
   PIN wl_0_44
      DIRECTION INPUT ;
      PORT
         LAYER M1 ;
         RECT  0.0 109.355 0.09 109.445 ;
      END
   END wl_0_44
   PIN wl_0_45
      DIRECTION INPUT ;
      PORT
         LAYER M1 ;
         RECT  0.0 112.895 0.09 112.985 ;
      END
   END wl_0_45
   PIN wl_0_46
      DIRECTION INPUT ;
      PORT
         LAYER M1 ;
         RECT  0.0 114.075 0.09 114.165 ;
      END
   END wl_0_46
   PIN wl_0_47
      DIRECTION INPUT ;
      PORT
         LAYER M1 ;
         RECT  0.0 117.615 0.09 117.705 ;
      END
   END wl_0_47
   PIN wl_0_48
      DIRECTION INPUT ;
      PORT
         LAYER M1 ;
         RECT  0.0 118.795 0.09 118.885 ;
      END
   END wl_0_48
   PIN wl_0_49
      DIRECTION INPUT ;
      PORT
         LAYER M1 ;
         RECT  0.0 122.335 0.09 122.425 ;
      END
   END wl_0_49
   PIN wl_0_50
      DIRECTION INPUT ;
      PORT
         LAYER M1 ;
         RECT  0.0 123.515 0.09 123.605 ;
      END
   END wl_0_50
   PIN wl_0_51
      DIRECTION INPUT ;
      PORT
         LAYER M1 ;
         RECT  0.0 127.055 0.09 127.145 ;
      END
   END wl_0_51
   PIN wl_0_52
      DIRECTION INPUT ;
      PORT
         LAYER M1 ;
         RECT  0.0 128.235 0.09 128.325 ;
      END
   END wl_0_52
   PIN wl_0_53
      DIRECTION INPUT ;
      PORT
         LAYER M1 ;
         RECT  0.0 131.775 0.09 131.865 ;
      END
   END wl_0_53
   PIN wl_0_54
      DIRECTION INPUT ;
      PORT
         LAYER M1 ;
         RECT  0.0 132.955 0.09 133.045 ;
      END
   END wl_0_54
   PIN wl_0_55
      DIRECTION INPUT ;
      PORT
         LAYER M1 ;
         RECT  0.0 136.495 0.09 136.585 ;
      END
   END wl_0_55
   PIN wl_0_56
      DIRECTION INPUT ;
      PORT
         LAYER M1 ;
         RECT  0.0 137.675 0.09 137.765 ;
      END
   END wl_0_56
   PIN wl_0_57
      DIRECTION INPUT ;
      PORT
         LAYER M1 ;
         RECT  0.0 141.215 0.09 141.305 ;
      END
   END wl_0_57
   PIN wl_0_58
      DIRECTION INPUT ;
      PORT
         LAYER M1 ;
         RECT  0.0 142.395 0.09 142.485 ;
      END
   END wl_0_58
   PIN wl_0_59
      DIRECTION INPUT ;
      PORT
         LAYER M1 ;
         RECT  0.0 145.935 0.09 146.025 ;
      END
   END wl_0_59
   PIN wl_0_60
      DIRECTION INPUT ;
      PORT
         LAYER M1 ;
         RECT  0.0 147.115 0.09 147.205 ;
      END
   END wl_0_60
   PIN wl_0_61
      DIRECTION INPUT ;
      PORT
         LAYER M1 ;
         RECT  0.0 150.655 0.09 150.745 ;
      END
   END wl_0_61
   PIN wl_0_62
      DIRECTION INPUT ;
      PORT
         LAYER M1 ;
         RECT  0.0 151.835 0.09 151.925 ;
      END
   END wl_0_62
   PIN wl_0_63
      DIRECTION INPUT ;
      PORT
         LAYER M1 ;
         RECT  0.0 155.375 0.09 155.465 ;
      END
   END wl_0_63
   PIN wl_0_64
      DIRECTION INPUT ;
      PORT
         LAYER M1 ;
         RECT  0.0 156.555 0.09 156.645 ;
      END
   END wl_0_64
   PIN wl_0_65
      DIRECTION INPUT ;
      PORT
         LAYER M1 ;
         RECT  0.0 160.095 0.09 160.185 ;
      END
   END wl_0_65
   PIN wl_0_66
      DIRECTION INPUT ;
      PORT
         LAYER M1 ;
         RECT  0.0 161.275 0.09 161.365 ;
      END
   END wl_0_66
   PIN wl_0_67
      DIRECTION INPUT ;
      PORT
         LAYER M1 ;
         RECT  0.0 164.815 0.09 164.905 ;
      END
   END wl_0_67
   PIN wl_0_68
      DIRECTION INPUT ;
      PORT
         LAYER M1 ;
         RECT  0.0 165.995 0.09 166.085 ;
      END
   END wl_0_68
   PIN wl_0_69
      DIRECTION INPUT ;
      PORT
         LAYER M1 ;
         RECT  0.0 169.535 0.09 169.625 ;
      END
   END wl_0_69
   PIN wl_0_70
      DIRECTION INPUT ;
      PORT
         LAYER M1 ;
         RECT  0.0 170.715 0.09 170.805 ;
      END
   END wl_0_70
   PIN wl_0_71
      DIRECTION INPUT ;
      PORT
         LAYER M1 ;
         RECT  0.0 174.255 0.09 174.345 ;
      END
   END wl_0_71
   PIN wl_0_72
      DIRECTION INPUT ;
      PORT
         LAYER M1 ;
         RECT  0.0 175.435 0.09 175.525 ;
      END
   END wl_0_72
   PIN wl_0_73
      DIRECTION INPUT ;
      PORT
         LAYER M1 ;
         RECT  0.0 178.975 0.09 179.065 ;
      END
   END wl_0_73
   PIN wl_0_74
      DIRECTION INPUT ;
      PORT
         LAYER M1 ;
         RECT  0.0 180.155 0.09 180.245 ;
      END
   END wl_0_74
   PIN wl_0_75
      DIRECTION INPUT ;
      PORT
         LAYER M1 ;
         RECT  0.0 183.695 0.09 183.785 ;
      END
   END wl_0_75
   PIN wl_0_76
      DIRECTION INPUT ;
      PORT
         LAYER M1 ;
         RECT  0.0 184.875 0.09 184.965 ;
      END
   END wl_0_76
   PIN wl_0_77
      DIRECTION INPUT ;
      PORT
         LAYER M1 ;
         RECT  0.0 188.415 0.09 188.505 ;
      END
   END wl_0_77
   PIN wl_0_78
      DIRECTION INPUT ;
      PORT
         LAYER M1 ;
         RECT  0.0 189.595 0.09 189.685 ;
      END
   END wl_0_78
   PIN wl_0_79
      DIRECTION INPUT ;
      PORT
         LAYER M1 ;
         RECT  0.0 193.135 0.09 193.225 ;
      END
   END wl_0_79
   PIN wl_0_80
      DIRECTION INPUT ;
      PORT
         LAYER M1 ;
         RECT  0.0 194.315 0.09 194.405 ;
      END
   END wl_0_80
   PIN wl_0_81
      DIRECTION INPUT ;
      PORT
         LAYER M1 ;
         RECT  0.0 197.855 0.09 197.945 ;
      END
   END wl_0_81
   PIN wl_0_82
      DIRECTION INPUT ;
      PORT
         LAYER M1 ;
         RECT  0.0 199.035 0.09 199.125 ;
      END
   END wl_0_82
   PIN wl_0_83
      DIRECTION INPUT ;
      PORT
         LAYER M1 ;
         RECT  0.0 202.575 0.09 202.665 ;
      END
   END wl_0_83
   PIN wl_0_84
      DIRECTION INPUT ;
      PORT
         LAYER M1 ;
         RECT  0.0 203.755 0.09 203.845 ;
      END
   END wl_0_84
   PIN wl_0_85
      DIRECTION INPUT ;
      PORT
         LAYER M1 ;
         RECT  0.0 207.295 0.09 207.385 ;
      END
   END wl_0_85
   PIN wl_0_86
      DIRECTION INPUT ;
      PORT
         LAYER M1 ;
         RECT  0.0 208.475 0.09 208.565 ;
      END
   END wl_0_86
   PIN wl_0_87
      DIRECTION INPUT ;
      PORT
         LAYER M1 ;
         RECT  0.0 212.015 0.09 212.105 ;
      END
   END wl_0_87
   PIN wl_0_88
      DIRECTION INPUT ;
      PORT
         LAYER M1 ;
         RECT  0.0 213.195 0.09 213.285 ;
      END
   END wl_0_88
   PIN wl_0_89
      DIRECTION INPUT ;
      PORT
         LAYER M1 ;
         RECT  0.0 216.735 0.09 216.825 ;
      END
   END wl_0_89
   PIN wl_0_90
      DIRECTION INPUT ;
      PORT
         LAYER M1 ;
         RECT  0.0 217.915 0.09 218.005 ;
      END
   END wl_0_90
   PIN wl_0_91
      DIRECTION INPUT ;
      PORT
         LAYER M1 ;
         RECT  0.0 221.455 0.09 221.545 ;
      END
   END wl_0_91
   PIN wl_0_92
      DIRECTION INPUT ;
      PORT
         LAYER M1 ;
         RECT  0.0 222.635 0.09 222.725 ;
      END
   END wl_0_92
   PIN wl_0_93
      DIRECTION INPUT ;
      PORT
         LAYER M1 ;
         RECT  0.0 226.175 0.09 226.265 ;
      END
   END wl_0_93
   PIN wl_0_94
      DIRECTION INPUT ;
      PORT
         LAYER M1 ;
         RECT  0.0 227.355 0.09 227.445 ;
      END
   END wl_0_94
   PIN wl_0_95
      DIRECTION INPUT ;
      PORT
         LAYER M1 ;
         RECT  0.0 230.895 0.09 230.985 ;
      END
   END wl_0_95
   PIN wl_0_96
      DIRECTION INPUT ;
      PORT
         LAYER M1 ;
         RECT  0.0 232.075 0.09 232.165 ;
      END
   END wl_0_96
   PIN wl_0_97
      DIRECTION INPUT ;
      PORT
         LAYER M1 ;
         RECT  0.0 235.615 0.09 235.705 ;
      END
   END wl_0_97
   PIN wl_0_98
      DIRECTION INPUT ;
      PORT
         LAYER M1 ;
         RECT  0.0 236.795 0.09 236.885 ;
      END
   END wl_0_98
   PIN wl_0_99
      DIRECTION INPUT ;
      PORT
         LAYER M1 ;
         RECT  0.0 240.335 0.09 240.425 ;
      END
   END wl_0_99
   PIN wl_0_100
      DIRECTION INPUT ;
      PORT
         LAYER M1 ;
         RECT  0.0 241.515 0.09 241.605 ;
      END
   END wl_0_100
   PIN wl_0_101
      DIRECTION INPUT ;
      PORT
         LAYER M1 ;
         RECT  0.0 245.055 0.09 245.145 ;
      END
   END wl_0_101
   PIN wl_0_102
      DIRECTION INPUT ;
      PORT
         LAYER M1 ;
         RECT  0.0 246.235 0.09 246.325 ;
      END
   END wl_0_102
   PIN wl_0_103
      DIRECTION INPUT ;
      PORT
         LAYER M1 ;
         RECT  0.0 249.775 0.09 249.865 ;
      END
   END wl_0_103
   PIN wl_0_104
      DIRECTION INPUT ;
      PORT
         LAYER M1 ;
         RECT  0.0 250.955 0.09 251.045 ;
      END
   END wl_0_104
   PIN wl_0_105
      DIRECTION INPUT ;
      PORT
         LAYER M1 ;
         RECT  0.0 254.495 0.09 254.585 ;
      END
   END wl_0_105
   PIN wl_0_106
      DIRECTION INPUT ;
      PORT
         LAYER M1 ;
         RECT  0.0 255.675 0.09 255.765 ;
      END
   END wl_0_106
   PIN wl_0_107
      DIRECTION INPUT ;
      PORT
         LAYER M1 ;
         RECT  0.0 259.215 0.09 259.305 ;
      END
   END wl_0_107
   PIN wl_0_108
      DIRECTION INPUT ;
      PORT
         LAYER M1 ;
         RECT  0.0 260.395 0.09 260.485 ;
      END
   END wl_0_108
   PIN wl_0_109
      DIRECTION INPUT ;
      PORT
         LAYER M1 ;
         RECT  0.0 263.935 0.09 264.025 ;
      END
   END wl_0_109
   PIN wl_0_110
      DIRECTION INPUT ;
      PORT
         LAYER M1 ;
         RECT  0.0 265.115 0.09 265.205 ;
      END
   END wl_0_110
   PIN wl_0_111
      DIRECTION INPUT ;
      PORT
         LAYER M1 ;
         RECT  0.0 268.655 0.09 268.745 ;
      END
   END wl_0_111
   PIN wl_0_112
      DIRECTION INPUT ;
      PORT
         LAYER M1 ;
         RECT  0.0 269.835 0.09 269.925 ;
      END
   END wl_0_112
   PIN wl_0_113
      DIRECTION INPUT ;
      PORT
         LAYER M1 ;
         RECT  0.0 273.375 0.09 273.465 ;
      END
   END wl_0_113
   PIN wl_0_114
      DIRECTION INPUT ;
      PORT
         LAYER M1 ;
         RECT  0.0 274.555 0.09 274.645 ;
      END
   END wl_0_114
   PIN wl_0_115
      DIRECTION INPUT ;
      PORT
         LAYER M1 ;
         RECT  0.0 278.095 0.09 278.185 ;
      END
   END wl_0_115
   PIN wl_0_116
      DIRECTION INPUT ;
      PORT
         LAYER M1 ;
         RECT  0.0 279.275 0.09 279.365 ;
      END
   END wl_0_116
   PIN wl_0_117
      DIRECTION INPUT ;
      PORT
         LAYER M1 ;
         RECT  0.0 282.815 0.09 282.905 ;
      END
   END wl_0_117
   PIN wl_0_118
      DIRECTION INPUT ;
      PORT
         LAYER M1 ;
         RECT  0.0 283.995 0.09 284.085 ;
      END
   END wl_0_118
   PIN wl_0_119
      DIRECTION INPUT ;
      PORT
         LAYER M1 ;
         RECT  0.0 287.535 0.09 287.625 ;
      END
   END wl_0_119
   PIN wl_0_120
      DIRECTION INPUT ;
      PORT
         LAYER M1 ;
         RECT  0.0 288.715 0.09 288.805 ;
      END
   END wl_0_120
   PIN wl_0_121
      DIRECTION INPUT ;
      PORT
         LAYER M1 ;
         RECT  0.0 292.255 0.09 292.345 ;
      END
   END wl_0_121
   PIN wl_0_122
      DIRECTION INPUT ;
      PORT
         LAYER M1 ;
         RECT  0.0 293.435 0.09 293.525 ;
      END
   END wl_0_122
   PIN wl_0_123
      DIRECTION INPUT ;
      PORT
         LAYER M1 ;
         RECT  0.0 296.975 0.09 297.065 ;
      END
   END wl_0_123
   PIN wl_0_124
      DIRECTION INPUT ;
      PORT
         LAYER M1 ;
         RECT  0.0 298.155 0.09 298.245 ;
      END
   END wl_0_124
   PIN wl_0_125
      DIRECTION INPUT ;
      PORT
         LAYER M1 ;
         RECT  0.0 301.695 0.09 301.785 ;
      END
   END wl_0_125
   PIN wl_0_126
      DIRECTION INPUT ;
      PORT
         LAYER M1 ;
         RECT  0.0 302.875 0.09 302.965 ;
      END
   END wl_0_126
   PIN wl_0_127
      DIRECTION INPUT ;
      PORT
         LAYER M1 ;
         RECT  0.0 306.415 0.09 306.505 ;
      END
   END wl_0_127
   PIN wl_0_128
      DIRECTION INPUT ;
      PORT
         LAYER M1 ;
         RECT  0.0 307.595 0.09 307.685 ;
      END
   END wl_0_128
   PIN wl_0_129
      DIRECTION INPUT ;
      PORT
         LAYER M1 ;
         RECT  0.0 311.135 0.09 311.225 ;
      END
   END wl_0_129
   PIN wl_0_130
      DIRECTION INPUT ;
      PORT
         LAYER M1 ;
         RECT  0.0 312.315 0.09 312.405 ;
      END
   END wl_0_130
   PIN wl_0_131
      DIRECTION INPUT ;
      PORT
         LAYER M1 ;
         RECT  0.0 315.855 0.09 315.945 ;
      END
   END wl_0_131
   PIN wl_0_132
      DIRECTION INPUT ;
      PORT
         LAYER M1 ;
         RECT  0.0 317.035 0.09 317.125 ;
      END
   END wl_0_132
   PIN wl_0_133
      DIRECTION INPUT ;
      PORT
         LAYER M1 ;
         RECT  0.0 320.575 0.09 320.665 ;
      END
   END wl_0_133
   PIN wl_0_134
      DIRECTION INPUT ;
      PORT
         LAYER M1 ;
         RECT  0.0 321.755 0.09 321.845 ;
      END
   END wl_0_134
   PIN wl_0_135
      DIRECTION INPUT ;
      PORT
         LAYER M1 ;
         RECT  0.0 325.295 0.09 325.385 ;
      END
   END wl_0_135
   PIN wl_0_136
      DIRECTION INPUT ;
      PORT
         LAYER M1 ;
         RECT  0.0 326.475 0.09 326.565 ;
      END
   END wl_0_136
   PIN wl_0_137
      DIRECTION INPUT ;
      PORT
         LAYER M1 ;
         RECT  0.0 330.015 0.09 330.105 ;
      END
   END wl_0_137
   PIN wl_0_138
      DIRECTION INPUT ;
      PORT
         LAYER M1 ;
         RECT  0.0 331.195 0.09 331.285 ;
      END
   END wl_0_138
   PIN wl_0_139
      DIRECTION INPUT ;
      PORT
         LAYER M1 ;
         RECT  0.0 334.735 0.09 334.825 ;
      END
   END wl_0_139
   PIN wl_0_140
      DIRECTION INPUT ;
      PORT
         LAYER M1 ;
         RECT  0.0 335.915 0.09 336.005 ;
      END
   END wl_0_140
   PIN wl_0_141
      DIRECTION INPUT ;
      PORT
         LAYER M1 ;
         RECT  0.0 339.455 0.09 339.545 ;
      END
   END wl_0_141
   PIN wl_0_142
      DIRECTION INPUT ;
      PORT
         LAYER M1 ;
         RECT  0.0 340.635 0.09 340.725 ;
      END
   END wl_0_142
   PIN wl_0_143
      DIRECTION INPUT ;
      PORT
         LAYER M1 ;
         RECT  0.0 344.175 0.09 344.265 ;
      END
   END wl_0_143
   PIN wl_0_144
      DIRECTION INPUT ;
      PORT
         LAYER M1 ;
         RECT  0.0 345.355 0.09 345.445 ;
      END
   END wl_0_144
   PIN wl_0_145
      DIRECTION INPUT ;
      PORT
         LAYER M1 ;
         RECT  0.0 348.895 0.09 348.985 ;
      END
   END wl_0_145
   PIN wl_0_146
      DIRECTION INPUT ;
      PORT
         LAYER M1 ;
         RECT  0.0 350.075 0.09 350.165 ;
      END
   END wl_0_146
   PIN wl_0_147
      DIRECTION INPUT ;
      PORT
         LAYER M1 ;
         RECT  0.0 353.615 0.09 353.705 ;
      END
   END wl_0_147
   PIN wl_0_148
      DIRECTION INPUT ;
      PORT
         LAYER M1 ;
         RECT  0.0 354.795 0.09 354.885 ;
      END
   END wl_0_148
   PIN wl_0_149
      DIRECTION INPUT ;
      PORT
         LAYER M1 ;
         RECT  0.0 358.335 0.09 358.425 ;
      END
   END wl_0_149
   PIN wl_0_150
      DIRECTION INPUT ;
      PORT
         LAYER M1 ;
         RECT  0.0 359.515 0.09 359.605 ;
      END
   END wl_0_150
   PIN wl_0_151
      DIRECTION INPUT ;
      PORT
         LAYER M1 ;
         RECT  0.0 363.055 0.09 363.145 ;
      END
   END wl_0_151
   PIN wl_0_152
      DIRECTION INPUT ;
      PORT
         LAYER M1 ;
         RECT  0.0 364.235 0.09 364.325 ;
      END
   END wl_0_152
   PIN wl_0_153
      DIRECTION INPUT ;
      PORT
         LAYER M1 ;
         RECT  0.0 367.775 0.09 367.865 ;
      END
   END wl_0_153
   PIN wl_0_154
      DIRECTION INPUT ;
      PORT
         LAYER M1 ;
         RECT  0.0 368.955 0.09 369.045 ;
      END
   END wl_0_154
   PIN wl_0_155
      DIRECTION INPUT ;
      PORT
         LAYER M1 ;
         RECT  0.0 372.495 0.09 372.585 ;
      END
   END wl_0_155
   PIN wl_0_156
      DIRECTION INPUT ;
      PORT
         LAYER M1 ;
         RECT  0.0 373.675 0.09 373.765 ;
      END
   END wl_0_156
   PIN wl_0_157
      DIRECTION INPUT ;
      PORT
         LAYER M1 ;
         RECT  0.0 377.215 0.09 377.305 ;
      END
   END wl_0_157
   PIN wl_0_158
      DIRECTION INPUT ;
      PORT
         LAYER M1 ;
         RECT  0.0 378.395 0.09 378.485 ;
      END
   END wl_0_158
   PIN wl_0_159
      DIRECTION INPUT ;
      PORT
         LAYER M1 ;
         RECT  0.0 381.935 0.09 382.025 ;
      END
   END wl_0_159
   PIN wl_0_160
      DIRECTION INPUT ;
      PORT
         LAYER M1 ;
         RECT  0.0 383.115 0.09 383.205 ;
      END
   END wl_0_160
   PIN wl_0_161
      DIRECTION INPUT ;
      PORT
         LAYER M1 ;
         RECT  0.0 386.655 0.09 386.745 ;
      END
   END wl_0_161
   PIN wl_0_162
      DIRECTION INPUT ;
      PORT
         LAYER M1 ;
         RECT  0.0 387.835 0.09 387.925 ;
      END
   END wl_0_162
   PIN wl_0_163
      DIRECTION INPUT ;
      PORT
         LAYER M1 ;
         RECT  0.0 391.375 0.09 391.465 ;
      END
   END wl_0_163
   PIN wl_0_164
      DIRECTION INPUT ;
      PORT
         LAYER M1 ;
         RECT  0.0 392.555 0.09 392.645 ;
      END
   END wl_0_164
   PIN wl_0_165
      DIRECTION INPUT ;
      PORT
         LAYER M1 ;
         RECT  0.0 396.095 0.09 396.185 ;
      END
   END wl_0_165
   PIN wl_0_166
      DIRECTION INPUT ;
      PORT
         LAYER M1 ;
         RECT  0.0 397.275 0.09 397.365 ;
      END
   END wl_0_166
   PIN wl_0_167
      DIRECTION INPUT ;
      PORT
         LAYER M1 ;
         RECT  0.0 400.815 0.09 400.905 ;
      END
   END wl_0_167
   PIN wl_0_168
      DIRECTION INPUT ;
      PORT
         LAYER M1 ;
         RECT  0.0 401.995 0.09 402.085 ;
      END
   END wl_0_168
   PIN wl_0_169
      DIRECTION INPUT ;
      PORT
         LAYER M1 ;
         RECT  0.0 405.535 0.09 405.625 ;
      END
   END wl_0_169
   PIN wl_0_170
      DIRECTION INPUT ;
      PORT
         LAYER M1 ;
         RECT  0.0 406.715 0.09 406.805 ;
      END
   END wl_0_170
   PIN wl_0_171
      DIRECTION INPUT ;
      PORT
         LAYER M1 ;
         RECT  0.0 410.255 0.09 410.345 ;
      END
   END wl_0_171
   PIN wl_0_172
      DIRECTION INPUT ;
      PORT
         LAYER M1 ;
         RECT  0.0 411.435 0.09 411.525 ;
      END
   END wl_0_172
   PIN wl_0_173
      DIRECTION INPUT ;
      PORT
         LAYER M1 ;
         RECT  0.0 414.975 0.09 415.065 ;
      END
   END wl_0_173
   PIN wl_0_174
      DIRECTION INPUT ;
      PORT
         LAYER M1 ;
         RECT  0.0 416.155 0.09 416.245 ;
      END
   END wl_0_174
   PIN wl_0_175
      DIRECTION INPUT ;
      PORT
         LAYER M1 ;
         RECT  0.0 419.695 0.09 419.785 ;
      END
   END wl_0_175
   PIN wl_0_176
      DIRECTION INPUT ;
      PORT
         LAYER M1 ;
         RECT  0.0 420.875 0.09 420.965 ;
      END
   END wl_0_176
   PIN wl_0_177
      DIRECTION INPUT ;
      PORT
         LAYER M1 ;
         RECT  0.0 424.415 0.09 424.505 ;
      END
   END wl_0_177
   PIN wl_0_178
      DIRECTION INPUT ;
      PORT
         LAYER M1 ;
         RECT  0.0 425.595 0.09 425.685 ;
      END
   END wl_0_178
   PIN wl_0_179
      DIRECTION INPUT ;
      PORT
         LAYER M1 ;
         RECT  0.0 429.135 0.09 429.225 ;
      END
   END wl_0_179
   PIN wl_0_180
      DIRECTION INPUT ;
      PORT
         LAYER M1 ;
         RECT  0.0 430.315 0.09 430.405 ;
      END
   END wl_0_180
   PIN wl_0_181
      DIRECTION INPUT ;
      PORT
         LAYER M1 ;
         RECT  0.0 433.855 0.09 433.945 ;
      END
   END wl_0_181
   PIN wl_0_182
      DIRECTION INPUT ;
      PORT
         LAYER M1 ;
         RECT  0.0 435.035 0.09 435.125 ;
      END
   END wl_0_182
   PIN wl_0_183
      DIRECTION INPUT ;
      PORT
         LAYER M1 ;
         RECT  0.0 438.575 0.09 438.665 ;
      END
   END wl_0_183
   PIN wl_0_184
      DIRECTION INPUT ;
      PORT
         LAYER M1 ;
         RECT  0.0 439.755 0.09 439.845 ;
      END
   END wl_0_184
   PIN wl_0_185
      DIRECTION INPUT ;
      PORT
         LAYER M1 ;
         RECT  0.0 443.295 0.09 443.385 ;
      END
   END wl_0_185
   PIN wl_0_186
      DIRECTION INPUT ;
      PORT
         LAYER M1 ;
         RECT  0.0 444.475 0.09 444.565 ;
      END
   END wl_0_186
   PIN wl_0_187
      DIRECTION INPUT ;
      PORT
         LAYER M1 ;
         RECT  0.0 448.015 0.09 448.105 ;
      END
   END wl_0_187
   PIN wl_0_188
      DIRECTION INPUT ;
      PORT
         LAYER M1 ;
         RECT  0.0 449.195 0.09 449.285 ;
      END
   END wl_0_188
   PIN wl_0_189
      DIRECTION INPUT ;
      PORT
         LAYER M1 ;
         RECT  0.0 452.735 0.09 452.825 ;
      END
   END wl_0_189
   PIN wl_0_190
      DIRECTION INPUT ;
      PORT
         LAYER M1 ;
         RECT  0.0 453.915 0.09 454.005 ;
      END
   END wl_0_190
   PIN wl_0_191
      DIRECTION INPUT ;
      PORT
         LAYER M1 ;
         RECT  0.0 457.455 0.09 457.545 ;
      END
   END wl_0_191
   PIN wl_0_192
      DIRECTION INPUT ;
      PORT
         LAYER M1 ;
         RECT  0.0 458.635 0.09 458.725 ;
      END
   END wl_0_192
   PIN wl_0_193
      DIRECTION INPUT ;
      PORT
         LAYER M1 ;
         RECT  0.0 462.175 0.09 462.265 ;
      END
   END wl_0_193
   PIN wl_0_194
      DIRECTION INPUT ;
      PORT
         LAYER M1 ;
         RECT  0.0 463.355 0.09 463.445 ;
      END
   END wl_0_194
   PIN wl_0_195
      DIRECTION INPUT ;
      PORT
         LAYER M1 ;
         RECT  0.0 466.895 0.09 466.985 ;
      END
   END wl_0_195
   PIN wl_0_196
      DIRECTION INPUT ;
      PORT
         LAYER M1 ;
         RECT  0.0 468.075 0.09 468.165 ;
      END
   END wl_0_196
   PIN wl_0_197
      DIRECTION INPUT ;
      PORT
         LAYER M1 ;
         RECT  0.0 471.615 0.09 471.705 ;
      END
   END wl_0_197
   PIN wl_0_198
      DIRECTION INPUT ;
      PORT
         LAYER M1 ;
         RECT  0.0 472.795 0.09 472.885 ;
      END
   END wl_0_198
   PIN wl_0_199
      DIRECTION INPUT ;
      PORT
         LAYER M1 ;
         RECT  0.0 476.335 0.09 476.425 ;
      END
   END wl_0_199
   PIN wl_0_200
      DIRECTION INPUT ;
      PORT
         LAYER M1 ;
         RECT  0.0 477.515 0.09 477.605 ;
      END
   END wl_0_200
   PIN wl_0_201
      DIRECTION INPUT ;
      PORT
         LAYER M1 ;
         RECT  0.0 481.055 0.09 481.145 ;
      END
   END wl_0_201
   PIN wl_0_202
      DIRECTION INPUT ;
      PORT
         LAYER M1 ;
         RECT  0.0 482.235 0.09 482.325 ;
      END
   END wl_0_202
   PIN wl_0_203
      DIRECTION INPUT ;
      PORT
         LAYER M1 ;
         RECT  0.0 485.775 0.09 485.865 ;
      END
   END wl_0_203
   PIN wl_0_204
      DIRECTION INPUT ;
      PORT
         LAYER M1 ;
         RECT  0.0 486.955 0.09 487.045 ;
      END
   END wl_0_204
   PIN wl_0_205
      DIRECTION INPUT ;
      PORT
         LAYER M1 ;
         RECT  0.0 490.495 0.09 490.585 ;
      END
   END wl_0_205
   PIN wl_0_206
      DIRECTION INPUT ;
      PORT
         LAYER M1 ;
         RECT  0.0 491.675 0.09 491.765 ;
      END
   END wl_0_206
   PIN wl_0_207
      DIRECTION INPUT ;
      PORT
         LAYER M1 ;
         RECT  0.0 495.215 0.09 495.305 ;
      END
   END wl_0_207
   PIN wl_0_208
      DIRECTION INPUT ;
      PORT
         LAYER M1 ;
         RECT  0.0 496.395 0.09 496.485 ;
      END
   END wl_0_208
   PIN wl_0_209
      DIRECTION INPUT ;
      PORT
         LAYER M1 ;
         RECT  0.0 499.935 0.09 500.025 ;
      END
   END wl_0_209
   PIN wl_0_210
      DIRECTION INPUT ;
      PORT
         LAYER M1 ;
         RECT  0.0 501.115 0.09 501.205 ;
      END
   END wl_0_210
   PIN wl_0_211
      DIRECTION INPUT ;
      PORT
         LAYER M1 ;
         RECT  0.0 504.655 0.09 504.745 ;
      END
   END wl_0_211
   PIN wl_0_212
      DIRECTION INPUT ;
      PORT
         LAYER M1 ;
         RECT  0.0 505.835 0.09 505.925 ;
      END
   END wl_0_212
   PIN wl_0_213
      DIRECTION INPUT ;
      PORT
         LAYER M1 ;
         RECT  0.0 509.375 0.09 509.465 ;
      END
   END wl_0_213
   PIN wl_0_214
      DIRECTION INPUT ;
      PORT
         LAYER M1 ;
         RECT  0.0 510.555 0.09 510.645 ;
      END
   END wl_0_214
   PIN wl_0_215
      DIRECTION INPUT ;
      PORT
         LAYER M1 ;
         RECT  0.0 514.095 0.09 514.185 ;
      END
   END wl_0_215
   PIN wl_0_216
      DIRECTION INPUT ;
      PORT
         LAYER M1 ;
         RECT  0.0 515.275 0.09 515.365 ;
      END
   END wl_0_216
   PIN wl_0_217
      DIRECTION INPUT ;
      PORT
         LAYER M1 ;
         RECT  0.0 518.815 0.09 518.905 ;
      END
   END wl_0_217
   PIN wl_0_218
      DIRECTION INPUT ;
      PORT
         LAYER M1 ;
         RECT  0.0 519.995 0.09 520.085 ;
      END
   END wl_0_218
   PIN wl_0_219
      DIRECTION INPUT ;
      PORT
         LAYER M1 ;
         RECT  0.0 523.535 0.09 523.625 ;
      END
   END wl_0_219
   PIN wl_0_220
      DIRECTION INPUT ;
      PORT
         LAYER M1 ;
         RECT  0.0 524.715 0.09 524.805 ;
      END
   END wl_0_220
   PIN wl_0_221
      DIRECTION INPUT ;
      PORT
         LAYER M1 ;
         RECT  0.0 528.255 0.09 528.345 ;
      END
   END wl_0_221
   PIN wl_0_222
      DIRECTION INPUT ;
      PORT
         LAYER M1 ;
         RECT  0.0 529.435 0.09 529.525 ;
      END
   END wl_0_222
   PIN wl_0_223
      DIRECTION INPUT ;
      PORT
         LAYER M1 ;
         RECT  0.0 532.975 0.09 533.065 ;
      END
   END wl_0_223
   PIN wl_0_224
      DIRECTION INPUT ;
      PORT
         LAYER M1 ;
         RECT  0.0 534.155 0.09 534.245 ;
      END
   END wl_0_224
   PIN wl_0_225
      DIRECTION INPUT ;
      PORT
         LAYER M1 ;
         RECT  0.0 537.695 0.09 537.785 ;
      END
   END wl_0_225
   PIN wl_0_226
      DIRECTION INPUT ;
      PORT
         LAYER M1 ;
         RECT  0.0 538.875 0.09 538.965 ;
      END
   END wl_0_226
   PIN wl_0_227
      DIRECTION INPUT ;
      PORT
         LAYER M1 ;
         RECT  0.0 542.415 0.09 542.505 ;
      END
   END wl_0_227
   PIN wl_0_228
      DIRECTION INPUT ;
      PORT
         LAYER M1 ;
         RECT  0.0 543.595 0.09 543.685 ;
      END
   END wl_0_228
   PIN wl_0_229
      DIRECTION INPUT ;
      PORT
         LAYER M1 ;
         RECT  0.0 547.135 0.09 547.225 ;
      END
   END wl_0_229
   PIN wl_0_230
      DIRECTION INPUT ;
      PORT
         LAYER M1 ;
         RECT  0.0 548.315 0.09 548.405 ;
      END
   END wl_0_230
   PIN wl_0_231
      DIRECTION INPUT ;
      PORT
         LAYER M1 ;
         RECT  0.0 551.855 0.09 551.945 ;
      END
   END wl_0_231
   PIN wl_0_232
      DIRECTION INPUT ;
      PORT
         LAYER M1 ;
         RECT  0.0 553.035 0.09 553.125 ;
      END
   END wl_0_232
   PIN wl_0_233
      DIRECTION INPUT ;
      PORT
         LAYER M1 ;
         RECT  0.0 556.575 0.09 556.665 ;
      END
   END wl_0_233
   PIN wl_0_234
      DIRECTION INPUT ;
      PORT
         LAYER M1 ;
         RECT  0.0 557.755 0.09 557.845 ;
      END
   END wl_0_234
   PIN wl_0_235
      DIRECTION INPUT ;
      PORT
         LAYER M1 ;
         RECT  0.0 561.295 0.09 561.385 ;
      END
   END wl_0_235
   PIN wl_0_236
      DIRECTION INPUT ;
      PORT
         LAYER M1 ;
         RECT  0.0 562.475 0.09 562.565 ;
      END
   END wl_0_236
   PIN wl_0_237
      DIRECTION INPUT ;
      PORT
         LAYER M1 ;
         RECT  0.0 566.015 0.09 566.105 ;
      END
   END wl_0_237
   PIN wl_0_238
      DIRECTION INPUT ;
      PORT
         LAYER M1 ;
         RECT  0.0 567.195 0.09 567.285 ;
      END
   END wl_0_238
   PIN wl_0_239
      DIRECTION INPUT ;
      PORT
         LAYER M1 ;
         RECT  0.0 570.735 0.09 570.825 ;
      END
   END wl_0_239
   PIN wl_0_240
      DIRECTION INPUT ;
      PORT
         LAYER M1 ;
         RECT  0.0 571.915 0.09 572.005 ;
      END
   END wl_0_240
   PIN wl_0_241
      DIRECTION INPUT ;
      PORT
         LAYER M1 ;
         RECT  0.0 575.455 0.09 575.545 ;
      END
   END wl_0_241
   PIN wl_0_242
      DIRECTION INPUT ;
      PORT
         LAYER M1 ;
         RECT  0.0 576.635 0.09 576.725 ;
      END
   END wl_0_242
   PIN wl_0_243
      DIRECTION INPUT ;
      PORT
         LAYER M1 ;
         RECT  0.0 580.175 0.09 580.265 ;
      END
   END wl_0_243
   PIN wl_0_244
      DIRECTION INPUT ;
      PORT
         LAYER M1 ;
         RECT  0.0 581.355 0.09 581.445 ;
      END
   END wl_0_244
   PIN wl_0_245
      DIRECTION INPUT ;
      PORT
         LAYER M1 ;
         RECT  0.0 584.895 0.09 584.985 ;
      END
   END wl_0_245
   PIN wl_0_246
      DIRECTION INPUT ;
      PORT
         LAYER M1 ;
         RECT  0.0 586.075 0.09 586.165 ;
      END
   END wl_0_246
   PIN wl_0_247
      DIRECTION INPUT ;
      PORT
         LAYER M1 ;
         RECT  0.0 589.615 0.09 589.705 ;
      END
   END wl_0_247
   PIN wl_0_248
      DIRECTION INPUT ;
      PORT
         LAYER M1 ;
         RECT  0.0 590.795 0.09 590.885 ;
      END
   END wl_0_248
   PIN wl_0_249
      DIRECTION INPUT ;
      PORT
         LAYER M1 ;
         RECT  0.0 594.335 0.09 594.425 ;
      END
   END wl_0_249
   PIN wl_0_250
      DIRECTION INPUT ;
      PORT
         LAYER M1 ;
         RECT  0.0 595.515 0.09 595.605 ;
      END
   END wl_0_250
   PIN wl_0_251
      DIRECTION INPUT ;
      PORT
         LAYER M1 ;
         RECT  0.0 599.055 0.09 599.145 ;
      END
   END wl_0_251
   PIN wl_0_252
      DIRECTION INPUT ;
      PORT
         LAYER M1 ;
         RECT  0.0 600.235 0.09 600.325 ;
      END
   END wl_0_252
   PIN wl_0_253
      DIRECTION INPUT ;
      PORT
         LAYER M1 ;
         RECT  0.0 603.775 0.09 603.865 ;
      END
   END wl_0_253
   PIN wl_0_254
      DIRECTION INPUT ;
      PORT
         LAYER M1 ;
         RECT  0.0 604.955 0.09 605.045 ;
      END
   END wl_0_254
   PIN wl_0_255
      DIRECTION INPUT ;
      PORT
         LAYER M1 ;
         RECT  0.0 608.495 0.09 608.585 ;
      END
   END wl_0_255
   PIN vdd
      DIRECTION INOUT ;
      USE POWER ; 
      SHAPE ABUTMENT ; 
      PORT
      END
   END vdd
   PIN gnd
      DIRECTION INOUT ;
      USE GROUND ; 
      SHAPE ABUTMENT ; 
      PORT
      END
   END gnd
   OBS
   LAYER  M1 ;
      RECT  0.32 0.32 0.33 4.095 ;
      RECT  0.33 0.32 293.37 4.095 ;
      RECT  0.33 4.095 293.37 4.665 ;
      RECT  0.33 4.665 293.37 611.22 ;
      RECT  0.32 4.665 0.33 5.275 ;
      RECT  0.32 5.845 0.33 8.815 ;
      RECT  0.32 9.385 0.33 9.995 ;
      RECT  0.32 10.565 0.33 13.535 ;
      RECT  0.32 14.105 0.33 14.715 ;
      RECT  0.32 15.285 0.33 18.255 ;
      RECT  0.32 18.825 0.33 19.435 ;
      RECT  0.32 20.005 0.33 22.975 ;
      RECT  0.32 23.545 0.33 24.155 ;
      RECT  0.32 24.725 0.33 27.695 ;
      RECT  0.32 28.265 0.33 28.875 ;
      RECT  0.32 29.445 0.33 32.415 ;
      RECT  0.32 32.985 0.33 33.595 ;
      RECT  0.32 34.165 0.33 37.135 ;
      RECT  0.32 37.705 0.33 38.315 ;
      RECT  0.32 38.885 0.33 41.855 ;
      RECT  0.32 42.425 0.33 43.035 ;
      RECT  0.32 43.605 0.33 46.575 ;
      RECT  0.32 47.145 0.33 47.755 ;
      RECT  0.32 48.325 0.33 51.295 ;
      RECT  0.32 51.865 0.33 52.475 ;
      RECT  0.32 53.045 0.33 56.015 ;
      RECT  0.32 56.585 0.33 57.195 ;
      RECT  0.32 57.765 0.33 60.735 ;
      RECT  0.32 61.305 0.33 61.915 ;
      RECT  0.32 62.485 0.33 65.455 ;
      RECT  0.32 66.025 0.33 66.635 ;
      RECT  0.32 67.205 0.33 70.175 ;
      RECT  0.32 70.745 0.33 71.355 ;
      RECT  0.32 71.925 0.33 74.895 ;
      RECT  0.32 75.465 0.33 76.075 ;
      RECT  0.32 76.645 0.33 79.615 ;
      RECT  0.32 80.185 0.33 80.795 ;
      RECT  0.32 81.365 0.33 84.335 ;
      RECT  0.32 84.905 0.33 85.515 ;
      RECT  0.32 86.085 0.33 89.055 ;
      RECT  0.32 89.625 0.33 90.235 ;
      RECT  0.32 90.805 0.33 93.775 ;
      RECT  0.32 94.345 0.33 94.955 ;
      RECT  0.32 95.525 0.33 98.495 ;
      RECT  0.32 99.065 0.33 99.675 ;
      RECT  0.32 100.245 0.33 103.215 ;
      RECT  0.32 103.785 0.33 104.395 ;
      RECT  0.32 104.965 0.33 107.935 ;
      RECT  0.32 108.505 0.33 109.115 ;
      RECT  0.32 109.685 0.33 112.655 ;
      RECT  0.32 113.225 0.33 113.835 ;
      RECT  0.32 114.405 0.33 117.375 ;
      RECT  0.32 117.945 0.33 118.555 ;
      RECT  0.32 119.125 0.33 122.095 ;
      RECT  0.32 122.665 0.33 123.275 ;
      RECT  0.32 123.845 0.33 126.815 ;
      RECT  0.32 127.385 0.33 127.995 ;
      RECT  0.32 128.565 0.33 131.535 ;
      RECT  0.32 132.105 0.33 132.715 ;
      RECT  0.32 133.285 0.33 136.255 ;
      RECT  0.32 136.825 0.33 137.435 ;
      RECT  0.32 138.005 0.33 140.975 ;
      RECT  0.32 141.545 0.33 142.155 ;
      RECT  0.32 142.725 0.33 145.695 ;
      RECT  0.32 146.265 0.33 146.875 ;
      RECT  0.32 147.445 0.33 150.415 ;
      RECT  0.32 150.985 0.33 151.595 ;
      RECT  0.32 152.165 0.33 155.135 ;
      RECT  0.32 155.705 0.33 156.315 ;
      RECT  0.32 156.885 0.33 159.855 ;
      RECT  0.32 160.425 0.33 161.035 ;
      RECT  0.32 161.605 0.33 164.575 ;
      RECT  0.32 165.145 0.33 165.755 ;
      RECT  0.32 166.325 0.33 169.295 ;
      RECT  0.32 169.865 0.33 170.475 ;
      RECT  0.32 171.045 0.33 174.015 ;
      RECT  0.32 174.585 0.33 175.195 ;
      RECT  0.32 175.765 0.33 178.735 ;
      RECT  0.32 179.305 0.33 179.915 ;
      RECT  0.32 180.485 0.33 183.455 ;
      RECT  0.32 184.025 0.33 184.635 ;
      RECT  0.32 185.205 0.33 188.175 ;
      RECT  0.32 188.745 0.33 189.355 ;
      RECT  0.32 189.925 0.33 192.895 ;
      RECT  0.32 193.465 0.33 194.075 ;
      RECT  0.32 194.645 0.33 197.615 ;
      RECT  0.32 198.185 0.33 198.795 ;
      RECT  0.32 199.365 0.33 202.335 ;
      RECT  0.32 202.905 0.33 203.515 ;
      RECT  0.32 204.085 0.33 207.055 ;
      RECT  0.32 207.625 0.33 208.235 ;
      RECT  0.32 208.805 0.33 211.775 ;
      RECT  0.32 212.345 0.33 212.955 ;
      RECT  0.32 213.525 0.33 216.495 ;
      RECT  0.32 217.065 0.33 217.675 ;
      RECT  0.32 218.245 0.33 221.215 ;
      RECT  0.32 221.785 0.33 222.395 ;
      RECT  0.32 222.965 0.33 225.935 ;
      RECT  0.32 226.505 0.33 227.115 ;
      RECT  0.32 227.685 0.33 230.655 ;
      RECT  0.32 231.225 0.33 231.835 ;
      RECT  0.32 232.405 0.33 235.375 ;
      RECT  0.32 235.945 0.33 236.555 ;
      RECT  0.32 237.125 0.33 240.095 ;
      RECT  0.32 240.665 0.33 241.275 ;
      RECT  0.32 241.845 0.33 244.815 ;
      RECT  0.32 245.385 0.33 245.995 ;
      RECT  0.32 246.565 0.33 249.535 ;
      RECT  0.32 250.105 0.33 250.715 ;
      RECT  0.32 251.285 0.33 254.255 ;
      RECT  0.32 254.825 0.33 255.435 ;
      RECT  0.32 256.005 0.33 258.975 ;
      RECT  0.32 259.545 0.33 260.155 ;
      RECT  0.32 260.725 0.33 263.695 ;
      RECT  0.32 264.265 0.33 264.875 ;
      RECT  0.32 265.445 0.33 268.415 ;
      RECT  0.32 268.985 0.33 269.595 ;
      RECT  0.32 270.165 0.33 273.135 ;
      RECT  0.32 273.705 0.33 274.315 ;
      RECT  0.32 274.885 0.33 277.855 ;
      RECT  0.32 278.425 0.33 279.035 ;
      RECT  0.32 279.605 0.33 282.575 ;
      RECT  0.32 283.145 0.33 283.755 ;
      RECT  0.32 284.325 0.33 287.295 ;
      RECT  0.32 287.865 0.33 288.475 ;
      RECT  0.32 289.045 0.33 292.015 ;
      RECT  0.32 292.585 0.33 293.195 ;
      RECT  0.32 293.765 0.33 296.735 ;
      RECT  0.32 297.305 0.33 297.915 ;
      RECT  0.32 298.485 0.33 301.455 ;
      RECT  0.32 302.025 0.33 302.635 ;
      RECT  0.32 303.205 0.33 306.175 ;
      RECT  0.32 306.745 0.33 307.355 ;
      RECT  0.32 307.925 0.33 310.895 ;
      RECT  0.32 311.465 0.33 312.075 ;
      RECT  0.32 312.645 0.33 315.615 ;
      RECT  0.32 316.185 0.33 316.795 ;
      RECT  0.32 317.365 0.33 320.335 ;
      RECT  0.32 320.905 0.33 321.515 ;
      RECT  0.32 322.085 0.33 325.055 ;
      RECT  0.32 325.625 0.33 326.235 ;
      RECT  0.32 326.805 0.33 329.775 ;
      RECT  0.32 330.345 0.33 330.955 ;
      RECT  0.32 331.525 0.33 334.495 ;
      RECT  0.32 335.065 0.33 335.675 ;
      RECT  0.32 336.245 0.33 339.215 ;
      RECT  0.32 339.785 0.33 340.395 ;
      RECT  0.32 340.965 0.33 343.935 ;
      RECT  0.32 344.505 0.33 345.115 ;
      RECT  0.32 345.685 0.33 348.655 ;
      RECT  0.32 349.225 0.33 349.835 ;
      RECT  0.32 350.405 0.33 353.375 ;
      RECT  0.32 353.945 0.33 354.555 ;
      RECT  0.32 355.125 0.33 358.095 ;
      RECT  0.32 358.665 0.33 359.275 ;
      RECT  0.32 359.845 0.33 362.815 ;
      RECT  0.32 363.385 0.33 363.995 ;
      RECT  0.32 364.565 0.33 367.535 ;
      RECT  0.32 368.105 0.33 368.715 ;
      RECT  0.32 369.285 0.33 372.255 ;
      RECT  0.32 372.825 0.33 373.435 ;
      RECT  0.32 374.005 0.33 376.975 ;
      RECT  0.32 377.545 0.33 378.155 ;
      RECT  0.32 378.725 0.33 381.695 ;
      RECT  0.32 382.265 0.33 382.875 ;
      RECT  0.32 383.445 0.33 386.415 ;
      RECT  0.32 386.985 0.33 387.595 ;
      RECT  0.32 388.165 0.33 391.135 ;
      RECT  0.32 391.705 0.33 392.315 ;
      RECT  0.32 392.885 0.33 395.855 ;
      RECT  0.32 396.425 0.33 397.035 ;
      RECT  0.32 397.605 0.33 400.575 ;
      RECT  0.32 401.145 0.33 401.755 ;
      RECT  0.32 402.325 0.33 405.295 ;
      RECT  0.32 405.865 0.33 406.475 ;
      RECT  0.32 407.045 0.33 410.015 ;
      RECT  0.32 410.585 0.33 411.195 ;
      RECT  0.32 411.765 0.33 414.735 ;
      RECT  0.32 415.305 0.33 415.915 ;
      RECT  0.32 416.485 0.33 419.455 ;
      RECT  0.32 420.025 0.33 420.635 ;
      RECT  0.32 421.205 0.33 424.175 ;
      RECT  0.32 424.745 0.33 425.355 ;
      RECT  0.32 425.925 0.33 428.895 ;
      RECT  0.32 429.465 0.33 430.075 ;
      RECT  0.32 430.645 0.33 433.615 ;
      RECT  0.32 434.185 0.33 434.795 ;
      RECT  0.32 435.365 0.33 438.335 ;
      RECT  0.32 438.905 0.33 439.515 ;
      RECT  0.32 440.085 0.33 443.055 ;
      RECT  0.32 443.625 0.33 444.235 ;
      RECT  0.32 444.805 0.33 447.775 ;
      RECT  0.32 448.345 0.33 448.955 ;
      RECT  0.32 449.525 0.33 452.495 ;
      RECT  0.32 453.065 0.33 453.675 ;
      RECT  0.32 454.245 0.33 457.215 ;
      RECT  0.32 457.785 0.33 458.395 ;
      RECT  0.32 458.965 0.33 461.935 ;
      RECT  0.32 462.505 0.33 463.115 ;
      RECT  0.32 463.685 0.33 466.655 ;
      RECT  0.32 467.225 0.33 467.835 ;
      RECT  0.32 468.405 0.33 471.375 ;
      RECT  0.32 471.945 0.33 472.555 ;
      RECT  0.32 473.125 0.33 476.095 ;
      RECT  0.32 476.665 0.33 477.275 ;
      RECT  0.32 477.845 0.33 480.815 ;
      RECT  0.32 481.385 0.33 481.995 ;
      RECT  0.32 482.565 0.33 485.535 ;
      RECT  0.32 486.105 0.33 486.715 ;
      RECT  0.32 487.285 0.33 490.255 ;
      RECT  0.32 490.825 0.33 491.435 ;
      RECT  0.32 492.005 0.33 494.975 ;
      RECT  0.32 495.545 0.33 496.155 ;
      RECT  0.32 496.725 0.33 499.695 ;
      RECT  0.32 500.265 0.33 500.875 ;
      RECT  0.32 501.445 0.33 504.415 ;
      RECT  0.32 504.985 0.33 505.595 ;
      RECT  0.32 506.165 0.33 509.135 ;
      RECT  0.32 509.705 0.33 510.315 ;
      RECT  0.32 510.885 0.33 513.855 ;
      RECT  0.32 514.425 0.33 515.035 ;
      RECT  0.32 515.605 0.33 518.575 ;
      RECT  0.32 519.145 0.33 519.755 ;
      RECT  0.32 520.325 0.33 523.295 ;
      RECT  0.32 523.865 0.33 524.475 ;
      RECT  0.32 525.045 0.33 528.015 ;
      RECT  0.32 528.585 0.33 529.195 ;
      RECT  0.32 529.765 0.33 532.735 ;
      RECT  0.32 533.305 0.33 533.915 ;
      RECT  0.32 534.485 0.33 537.455 ;
      RECT  0.32 538.025 0.33 538.635 ;
      RECT  0.32 539.205 0.33 542.175 ;
      RECT  0.32 542.745 0.33 543.355 ;
      RECT  0.32 543.925 0.33 546.895 ;
      RECT  0.32 547.465 0.33 548.075 ;
      RECT  0.32 548.645 0.33 551.615 ;
      RECT  0.32 552.185 0.33 552.795 ;
      RECT  0.32 553.365 0.33 556.335 ;
      RECT  0.32 556.905 0.33 557.515 ;
      RECT  0.32 558.085 0.33 561.055 ;
      RECT  0.32 561.625 0.33 562.235 ;
      RECT  0.32 562.805 0.33 565.775 ;
      RECT  0.32 566.345 0.33 566.955 ;
      RECT  0.32 567.525 0.33 570.495 ;
      RECT  0.32 571.065 0.33 571.675 ;
      RECT  0.32 572.245 0.33 575.215 ;
      RECT  0.32 575.785 0.33 576.395 ;
      RECT  0.32 576.965 0.33 579.935 ;
      RECT  0.32 580.505 0.33 581.115 ;
      RECT  0.32 581.685 0.33 584.655 ;
      RECT  0.32 585.225 0.33 585.835 ;
      RECT  0.32 586.405 0.33 589.375 ;
      RECT  0.32 589.945 0.33 590.555 ;
      RECT  0.32 591.125 0.33 594.095 ;
      RECT  0.32 594.665 0.33 595.275 ;
      RECT  0.32 595.845 0.33 598.815 ;
      RECT  0.32 599.385 0.33 599.995 ;
      RECT  0.32 600.565 0.33 603.535 ;
      RECT  0.32 604.105 0.33 604.715 ;
      RECT  0.32 605.285 0.33 608.255 ;
      RECT  0.32 608.825 0.33 611.22 ;
   LAYER  M2 ;
      RECT  0.32 0.32 293.37 611.22 ;
   LAYER  M3 ;
      RECT  0.32 0.32 293.37 611.22 ;
   LAYER  M4 ;
      RECT  0.32 0.32 293.37 611.22 ;
   END
END    sram_32_1024_1rw_tsmc65N_tsmc65N_capped_replica_bitcell_array
END    LIBRARY
